VERSION 5.8 ;
BUSBITCHARS "[]" ;
DIVIDERCHAR "/" ;
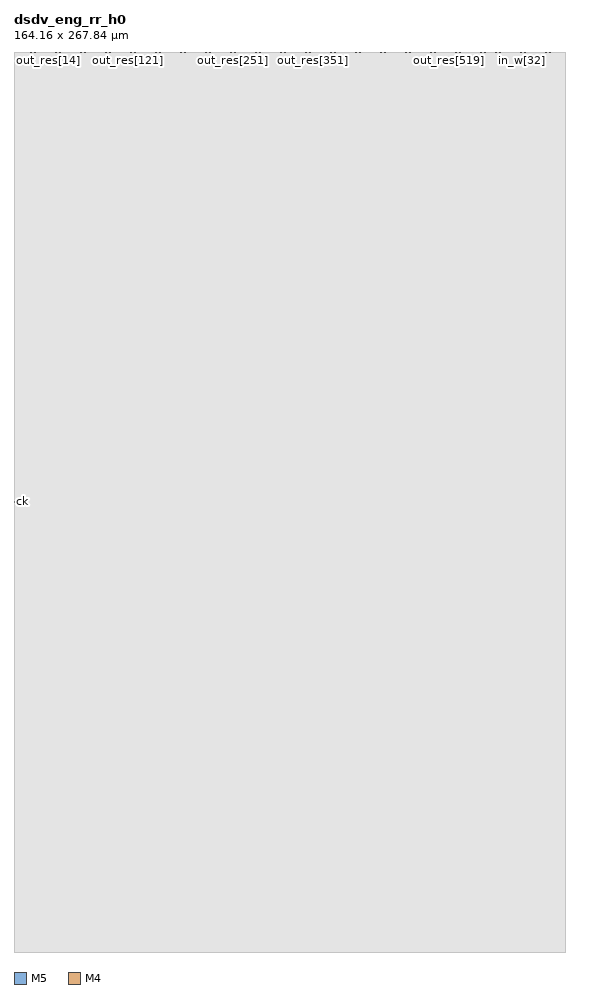
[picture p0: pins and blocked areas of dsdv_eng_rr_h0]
MACRO dsdv_eng_rr_h0
  CLASS BLOCK ;
  ORIGIN 0 0 ;
  FOREIGN dsdv_eng_rr_h0 0 0 ;
  SIZE 164.160 BY 267.840 ;
  SYMMETRY X Y ;
  PIN out_res[0]
    DIRECTION OUTPUT ;
    USE SIGNAL ;
    PORT
      LAYER M5 ;
        RECT 4.800 267.648 4.824 267.840 ;
    END
  END out_res[0]
  PIN out_res[1]
    DIRECTION OUTPUT ;
    USE SIGNAL ;
    PORT
      LAYER M5 ;
        RECT 5.040 267.648 5.064 267.840 ;
    END
  END out_res[1]
  PIN out_res[2]
    DIRECTION OUTPUT ;
    USE SIGNAL ;
    PORT
      LAYER M5 ;
        RECT 5.280 267.648 5.304 267.840 ;
    END
  END out_res[2]
  PIN out_res[3]
    DIRECTION OUTPUT ;
    USE SIGNAL ;
    PORT
      LAYER M5 ;
        RECT 5.520 267.648 5.544 267.840 ;
    END
  END out_res[3]
  PIN out_res[4]
    DIRECTION OUTPUT ;
    USE SIGNAL ;
    PORT
      LAYER M5 ;
        RECT 5.760 267.648 5.784 267.840 ;
    END
  END out_res[4]
  PIN out_res[5]
    DIRECTION OUTPUT ;
    USE SIGNAL ;
    PORT
      LAYER M5 ;
        RECT 6.000 267.648 6.024 267.840 ;
    END
  END out_res[5]
  PIN out_res[6]
    DIRECTION OUTPUT ;
    USE SIGNAL ;
    PORT
      LAYER M5 ;
        RECT 6.240 267.648 6.264 267.840 ;
    END
  END out_res[6]
  PIN out_res[7]
    DIRECTION OUTPUT ;
    USE SIGNAL ;
    PORT
      LAYER M5 ;
        RECT 6.480 267.648 6.504 267.840 ;
    END
  END out_res[7]
  PIN out_res[8]
    DIRECTION OUTPUT ;
    USE SIGNAL ;
    PORT
      LAYER M5 ;
        RECT 6.720 267.648 6.744 267.840 ;
    END
  END out_res[8]
  PIN out_res[9]
    DIRECTION OUTPUT ;
    USE SIGNAL ;
    PORT
      LAYER M5 ;
        RECT 6.960 267.648 6.984 267.840 ;
    END
  END out_res[9]
  PIN out_res[10]
    DIRECTION OUTPUT ;
    USE SIGNAL ;
    PORT
      LAYER M5 ;
        RECT 7.200 267.648 7.224 267.840 ;
    END
  END out_res[10]
  PIN out_res[11]
    DIRECTION OUTPUT ;
    USE SIGNAL ;
    PORT
      LAYER M5 ;
        RECT 7.440 267.648 7.464 267.840 ;
    END
  END out_res[11]
  PIN out_res[12]
    DIRECTION OUTPUT ;
    USE SIGNAL ;
    PORT
      LAYER M5 ;
        RECT 7.680 267.648 7.704 267.840 ;
    END
  END out_res[12]
  PIN out_res[13]
    DIRECTION OUTPUT ;
    USE SIGNAL ;
    PORT
      LAYER M5 ;
        RECT 7.920 267.648 7.944 267.840 ;
    END
  END out_res[13]
  PIN out_res[14]
    DIRECTION OUTPUT ;
    USE SIGNAL ;
    PORT
      LAYER M5 ;
        RECT 8.160 267.648 8.184 267.840 ;
    END
  END out_res[14]
  PIN out_res[15]
    DIRECTION OUTPUT ;
    USE SIGNAL ;
    PORT
      LAYER M5 ;
        RECT 8.400 267.648 8.424 267.840 ;
    END
  END out_res[15]
  PIN out_res[16]
    DIRECTION OUTPUT ;
    USE SIGNAL ;
    PORT
      LAYER M5 ;
        RECT 8.640 267.648 8.664 267.840 ;
    END
  END out_res[16]
  PIN out_res[17]
    DIRECTION OUTPUT ;
    USE SIGNAL ;
    PORT
      LAYER M5 ;
        RECT 8.880 267.648 8.904 267.840 ;
    END
  END out_res[17]
  PIN out_res[18]
    DIRECTION OUTPUT ;
    USE SIGNAL ;
    PORT
      LAYER M5 ;
        RECT 9.120 267.648 9.144 267.840 ;
    END
  END out_res[18]
  PIN out_res[19]
    DIRECTION OUTPUT ;
    USE SIGNAL ;
    PORT
      LAYER M5 ;
        RECT 9.360 267.648 9.384 267.840 ;
    END
  END out_res[19]
  PIN out_res[20]
    DIRECTION OUTPUT ;
    USE SIGNAL ;
    PORT
      LAYER M5 ;
        RECT 9.600 267.648 9.624 267.840 ;
    END
  END out_res[20]
  PIN out_res[21]
    DIRECTION OUTPUT ;
    USE SIGNAL ;
    PORT
      LAYER M5 ;
        RECT 9.840 267.648 9.864 267.840 ;
    END
  END out_res[21]
  PIN out_res[22]
    DIRECTION OUTPUT ;
    USE SIGNAL ;
    PORT
      LAYER M5 ;
        RECT 10.080 267.648 10.104 267.840 ;
    END
  END out_res[22]
  PIN out_res[23]
    DIRECTION OUTPUT ;
    USE SIGNAL ;
    PORT
      LAYER M5 ;
        RECT 10.320 267.648 10.344 267.840 ;
    END
  END out_res[23]
  PIN out_res[24]
    DIRECTION OUTPUT ;
    USE SIGNAL ;
    PORT
      LAYER M5 ;
        RECT 10.560 267.648 10.584 267.840 ;
    END
  END out_res[24]
  PIN out_res[25]
    DIRECTION OUTPUT ;
    USE SIGNAL ;
    PORT
      LAYER M5 ;
        RECT 10.800 267.648 10.824 267.840 ;
    END
  END out_res[25]
  PIN out_res[26]
    DIRECTION OUTPUT ;
    USE SIGNAL ;
    PORT
      LAYER M5 ;
        RECT 11.040 267.648 11.064 267.840 ;
    END
  END out_res[26]
  PIN out_res[27]
    DIRECTION OUTPUT ;
    USE SIGNAL ;
    PORT
      LAYER M5 ;
        RECT 11.280 267.648 11.304 267.840 ;
    END
  END out_res[27]
  PIN out_res[28]
    DIRECTION OUTPUT ;
    USE SIGNAL ;
    PORT
      LAYER M5 ;
        RECT 11.520 267.648 11.544 267.840 ;
    END
  END out_res[28]
  PIN out_res[29]
    DIRECTION OUTPUT ;
    USE SIGNAL ;
    PORT
      LAYER M5 ;
        RECT 11.760 267.648 11.784 267.840 ;
    END
  END out_res[29]
  PIN out_res[30]
    DIRECTION OUTPUT ;
    USE SIGNAL ;
    PORT
      LAYER M5 ;
        RECT 12.000 267.648 12.024 267.840 ;
    END
  END out_res[30]
  PIN out_res[31]
    DIRECTION OUTPUT ;
    USE SIGNAL ;
    PORT
      LAYER M5 ;
        RECT 12.240 267.648 12.264 267.840 ;
    END
  END out_res[31]
  PIN out_res[32]
    DIRECTION OUTPUT ;
    USE SIGNAL ;
    PORT
      LAYER M5 ;
        RECT 12.480 267.648 12.504 267.840 ;
    END
  END out_res[32]
  PIN out_res[33]
    DIRECTION OUTPUT ;
    USE SIGNAL ;
    PORT
      LAYER M5 ;
        RECT 12.720 267.648 12.744 267.840 ;
    END
  END out_res[33]
  PIN out_res[34]
    DIRECTION OUTPUT ;
    USE SIGNAL ;
    PORT
      LAYER M5 ;
        RECT 12.960 267.648 12.984 267.840 ;
    END
  END out_res[34]
  PIN out_res[35]
    DIRECTION OUTPUT ;
    USE SIGNAL ;
    PORT
      LAYER M5 ;
        RECT 13.200 267.648 13.224 267.840 ;
    END
  END out_res[35]
  PIN out_res[36]
    DIRECTION OUTPUT ;
    USE SIGNAL ;
    PORT
      LAYER M5 ;
        RECT 13.440 267.648 13.464 267.840 ;
    END
  END out_res[36]
  PIN out_res[37]
    DIRECTION OUTPUT ;
    USE SIGNAL ;
    PORT
      LAYER M5 ;
        RECT 13.680 267.648 13.704 267.840 ;
    END
  END out_res[37]
  PIN out_res[38]
    DIRECTION OUTPUT ;
    USE SIGNAL ;
    PORT
      LAYER M5 ;
        RECT 13.920 267.648 13.944 267.840 ;
    END
  END out_res[38]
  PIN out_res[39]
    DIRECTION OUTPUT ;
    USE SIGNAL ;
    PORT
      LAYER M5 ;
        RECT 14.160 267.648 14.184 267.840 ;
    END
  END out_res[39]
  PIN out_res[40]
    DIRECTION OUTPUT ;
    USE SIGNAL ;
    PORT
      LAYER M5 ;
        RECT 14.400 267.648 14.424 267.840 ;
    END
  END out_res[40]
  PIN out_res[41]
    DIRECTION OUTPUT ;
    USE SIGNAL ;
    PORT
      LAYER M5 ;
        RECT 14.640 267.648 14.664 267.840 ;
    END
  END out_res[41]
  PIN out_res[42]
    DIRECTION OUTPUT ;
    USE SIGNAL ;
    PORT
      LAYER M5 ;
        RECT 14.880 267.648 14.904 267.840 ;
    END
  END out_res[42]
  PIN out_res[43]
    DIRECTION OUTPUT ;
    USE SIGNAL ;
    PORT
      LAYER M5 ;
        RECT 15.120 267.648 15.144 267.840 ;
    END
  END out_res[43]
  PIN out_res[44]
    DIRECTION OUTPUT ;
    USE SIGNAL ;
    PORT
      LAYER M5 ;
        RECT 15.360 267.648 15.384 267.840 ;
    END
  END out_res[44]
  PIN out_res[45]
    DIRECTION OUTPUT ;
    USE SIGNAL ;
    PORT
      LAYER M5 ;
        RECT 15.600 267.648 15.624 267.840 ;
    END
  END out_res[45]
  PIN out_res[46]
    DIRECTION OUTPUT ;
    USE SIGNAL ;
    PORT
      LAYER M5 ;
        RECT 15.840 267.648 15.864 267.840 ;
    END
  END out_res[46]
  PIN out_res[47]
    DIRECTION OUTPUT ;
    USE SIGNAL ;
    PORT
      LAYER M5 ;
        RECT 16.080 267.648 16.104 267.840 ;
    END
  END out_res[47]
  PIN out_res[48]
    DIRECTION OUTPUT ;
    USE SIGNAL ;
    PORT
      LAYER M5 ;
        RECT 16.320 267.648 16.344 267.840 ;
    END
  END out_res[48]
  PIN out_res[49]
    DIRECTION OUTPUT ;
    USE SIGNAL ;
    PORT
      LAYER M5 ;
        RECT 16.560 267.648 16.584 267.840 ;
    END
  END out_res[49]
  PIN out_res[50]
    DIRECTION OUTPUT ;
    USE SIGNAL ;
    PORT
      LAYER M5 ;
        RECT 16.800 267.648 16.824 267.840 ;
    END
  END out_res[50]
  PIN out_res[51]
    DIRECTION OUTPUT ;
    USE SIGNAL ;
    PORT
      LAYER M5 ;
        RECT 17.040 267.648 17.064 267.840 ;
    END
  END out_res[51]
  PIN out_res[52]
    DIRECTION OUTPUT ;
    USE SIGNAL ;
    PORT
      LAYER M5 ;
        RECT 17.280 267.648 17.304 267.840 ;
    END
  END out_res[52]
  PIN out_res[53]
    DIRECTION OUTPUT ;
    USE SIGNAL ;
    PORT
      LAYER M5 ;
        RECT 17.520 267.648 17.544 267.840 ;
    END
  END out_res[53]
  PIN out_res[54]
    DIRECTION OUTPUT ;
    USE SIGNAL ;
    PORT
      LAYER M5 ;
        RECT 17.760 267.648 17.784 267.840 ;
    END
  END out_res[54]
  PIN out_res[55]
    DIRECTION OUTPUT ;
    USE SIGNAL ;
    PORT
      LAYER M5 ;
        RECT 18.000 267.648 18.024 267.840 ;
    END
  END out_res[55]
  PIN out_res[56]
    DIRECTION OUTPUT ;
    USE SIGNAL ;
    PORT
      LAYER M5 ;
        RECT 18.240 267.648 18.264 267.840 ;
    END
  END out_res[56]
  PIN out_res[57]
    DIRECTION OUTPUT ;
    USE SIGNAL ;
    PORT
      LAYER M5 ;
        RECT 18.480 267.648 18.504 267.840 ;
    END
  END out_res[57]
  PIN out_res[58]
    DIRECTION OUTPUT ;
    USE SIGNAL ;
    PORT
      LAYER M5 ;
        RECT 18.720 267.648 18.744 267.840 ;
    END
  END out_res[58]
  PIN out_res[59]
    DIRECTION OUTPUT ;
    USE SIGNAL ;
    PORT
      LAYER M5 ;
        RECT 18.960 267.648 18.984 267.840 ;
    END
  END out_res[59]
  PIN out_res[60]
    DIRECTION OUTPUT ;
    USE SIGNAL ;
    PORT
      LAYER M5 ;
        RECT 19.200 267.648 19.224 267.840 ;
    END
  END out_res[60]
  PIN out_res[61]
    DIRECTION OUTPUT ;
    USE SIGNAL ;
    PORT
      LAYER M5 ;
        RECT 19.440 267.648 19.464 267.840 ;
    END
  END out_res[61]
  PIN out_res[62]
    DIRECTION OUTPUT ;
    USE SIGNAL ;
    PORT
      LAYER M5 ;
        RECT 19.680 267.648 19.704 267.840 ;
    END
  END out_res[62]
  PIN out_res[63]
    DIRECTION OUTPUT ;
    USE SIGNAL ;
    PORT
      LAYER M5 ;
        RECT 19.920 267.648 19.944 267.840 ;
    END
  END out_res[63]
  PIN out_res[64]
    DIRECTION OUTPUT ;
    USE SIGNAL ;
    PORT
      LAYER M5 ;
        RECT 20.160 267.648 20.184 267.840 ;
    END
  END out_res[64]
  PIN out_res[65]
    DIRECTION OUTPUT ;
    USE SIGNAL ;
    PORT
      LAYER M5 ;
        RECT 20.400 267.648 20.424 267.840 ;
    END
  END out_res[65]
  PIN out_res[66]
    DIRECTION OUTPUT ;
    USE SIGNAL ;
    PORT
      LAYER M5 ;
        RECT 20.640 267.648 20.664 267.840 ;
    END
  END out_res[66]
  PIN out_res[67]
    DIRECTION OUTPUT ;
    USE SIGNAL ;
    PORT
      LAYER M5 ;
        RECT 20.880 267.648 20.904 267.840 ;
    END
  END out_res[67]
  PIN out_res[68]
    DIRECTION OUTPUT ;
    USE SIGNAL ;
    PORT
      LAYER M5 ;
        RECT 21.120 267.648 21.144 267.840 ;
    END
  END out_res[68]
  PIN out_res[69]
    DIRECTION OUTPUT ;
    USE SIGNAL ;
    PORT
      LAYER M5 ;
        RECT 21.360 267.648 21.384 267.840 ;
    END
  END out_res[69]
  PIN out_res[70]
    DIRECTION OUTPUT ;
    USE SIGNAL ;
    PORT
      LAYER M5 ;
        RECT 21.600 267.648 21.624 267.840 ;
    END
  END out_res[70]
  PIN out_res[71]
    DIRECTION OUTPUT ;
    USE SIGNAL ;
    PORT
      LAYER M5 ;
        RECT 21.840 267.648 21.864 267.840 ;
    END
  END out_res[71]
  PIN out_res[72]
    DIRECTION OUTPUT ;
    USE SIGNAL ;
    PORT
      LAYER M5 ;
        RECT 22.080 267.648 22.104 267.840 ;
    END
  END out_res[72]
  PIN out_res[73]
    DIRECTION OUTPUT ;
    USE SIGNAL ;
    PORT
      LAYER M5 ;
        RECT 22.320 267.648 22.344 267.840 ;
    END
  END out_res[73]
  PIN out_res[74]
    DIRECTION OUTPUT ;
    USE SIGNAL ;
    PORT
      LAYER M5 ;
        RECT 22.560 267.648 22.584 267.840 ;
    END
  END out_res[74]
  PIN out_res[75]
    DIRECTION OUTPUT ;
    USE SIGNAL ;
    PORT
      LAYER M5 ;
        RECT 22.800 267.648 22.824 267.840 ;
    END
  END out_res[75]
  PIN out_res[76]
    DIRECTION OUTPUT ;
    USE SIGNAL ;
    PORT
      LAYER M5 ;
        RECT 23.040 267.648 23.064 267.840 ;
    END
  END out_res[76]
  PIN out_res[77]
    DIRECTION OUTPUT ;
    USE SIGNAL ;
    PORT
      LAYER M5 ;
        RECT 23.280 267.648 23.304 267.840 ;
    END
  END out_res[77]
  PIN out_res[78]
    DIRECTION OUTPUT ;
    USE SIGNAL ;
    PORT
      LAYER M5 ;
        RECT 23.520 267.648 23.544 267.840 ;
    END
  END out_res[78]
  PIN out_res[79]
    DIRECTION OUTPUT ;
    USE SIGNAL ;
    PORT
      LAYER M5 ;
        RECT 23.760 267.648 23.784 267.840 ;
    END
  END out_res[79]
  PIN out_res[80]
    DIRECTION OUTPUT ;
    USE SIGNAL ;
    PORT
      LAYER M5 ;
        RECT 24.000 267.648 24.024 267.840 ;
    END
  END out_res[80]
  PIN out_res[81]
    DIRECTION OUTPUT ;
    USE SIGNAL ;
    PORT
      LAYER M5 ;
        RECT 24.240 267.648 24.264 267.840 ;
    END
  END out_res[81]
  PIN out_res[82]
    DIRECTION OUTPUT ;
    USE SIGNAL ;
    PORT
      LAYER M5 ;
        RECT 24.480 267.648 24.504 267.840 ;
    END
  END out_res[82]
  PIN out_res[83]
    DIRECTION OUTPUT ;
    USE SIGNAL ;
    PORT
      LAYER M5 ;
        RECT 24.720 267.648 24.744 267.840 ;
    END
  END out_res[83]
  PIN out_res[84]
    DIRECTION OUTPUT ;
    USE SIGNAL ;
    PORT
      LAYER M5 ;
        RECT 24.960 267.648 24.984 267.840 ;
    END
  END out_res[84]
  PIN out_res[85]
    DIRECTION OUTPUT ;
    USE SIGNAL ;
    PORT
      LAYER M5 ;
        RECT 25.200 267.648 25.224 267.840 ;
    END
  END out_res[85]
  PIN out_res[86]
    DIRECTION OUTPUT ;
    USE SIGNAL ;
    PORT
      LAYER M5 ;
        RECT 25.440 267.648 25.464 267.840 ;
    END
  END out_res[86]
  PIN out_res[87]
    DIRECTION OUTPUT ;
    USE SIGNAL ;
    PORT
      LAYER M5 ;
        RECT 25.680 267.648 25.704 267.840 ;
    END
  END out_res[87]
  PIN out_res[88]
    DIRECTION OUTPUT ;
    USE SIGNAL ;
    PORT
      LAYER M5 ;
        RECT 25.920 267.648 25.944 267.840 ;
    END
  END out_res[88]
  PIN out_res[89]
    DIRECTION OUTPUT ;
    USE SIGNAL ;
    PORT
      LAYER M5 ;
        RECT 26.160 267.648 26.184 267.840 ;
    END
  END out_res[89]
  PIN out_res[90]
    DIRECTION OUTPUT ;
    USE SIGNAL ;
    PORT
      LAYER M5 ;
        RECT 26.400 267.648 26.424 267.840 ;
    END
  END out_res[90]
  PIN out_res[91]
    DIRECTION OUTPUT ;
    USE SIGNAL ;
    PORT
      LAYER M5 ;
        RECT 26.640 267.648 26.664 267.840 ;
    END
  END out_res[91]
  PIN out_res[92]
    DIRECTION OUTPUT ;
    USE SIGNAL ;
    PORT
      LAYER M5 ;
        RECT 26.880 267.648 26.904 267.840 ;
    END
  END out_res[92]
  PIN out_res[93]
    DIRECTION OUTPUT ;
    USE SIGNAL ;
    PORT
      LAYER M5 ;
        RECT 27.120 267.648 27.144 267.840 ;
    END
  END out_res[93]
  PIN out_res[94]
    DIRECTION OUTPUT ;
    USE SIGNAL ;
    PORT
      LAYER M5 ;
        RECT 27.360 267.648 27.384 267.840 ;
    END
  END out_res[94]
  PIN out_res[95]
    DIRECTION OUTPUT ;
    USE SIGNAL ;
    PORT
      LAYER M5 ;
        RECT 27.600 267.648 27.624 267.840 ;
    END
  END out_res[95]
  PIN out_res[96]
    DIRECTION OUTPUT ;
    USE SIGNAL ;
    PORT
      LAYER M5 ;
        RECT 27.840 267.648 27.864 267.840 ;
    END
  END out_res[96]
  PIN out_res[97]
    DIRECTION OUTPUT ;
    USE SIGNAL ;
    PORT
      LAYER M5 ;
        RECT 28.080 267.648 28.104 267.840 ;
    END
  END out_res[97]
  PIN out_res[98]
    DIRECTION OUTPUT ;
    USE SIGNAL ;
    PORT
      LAYER M5 ;
        RECT 28.320 267.648 28.344 267.840 ;
    END
  END out_res[98]
  PIN out_res[99]
    DIRECTION OUTPUT ;
    USE SIGNAL ;
    PORT
      LAYER M5 ;
        RECT 28.560 267.648 28.584 267.840 ;
    END
  END out_res[99]
  PIN out_res[100]
    DIRECTION OUTPUT ;
    USE SIGNAL ;
    PORT
      LAYER M5 ;
        RECT 28.800 267.648 28.824 267.840 ;
    END
  END out_res[100]
  PIN out_res[101]
    DIRECTION OUTPUT ;
    USE SIGNAL ;
    PORT
      LAYER M5 ;
        RECT 29.040 267.648 29.064 267.840 ;
    END
  END out_res[101]
  PIN out_res[102]
    DIRECTION OUTPUT ;
    USE SIGNAL ;
    PORT
      LAYER M5 ;
        RECT 29.280 267.648 29.304 267.840 ;
    END
  END out_res[102]
  PIN out_res[103]
    DIRECTION OUTPUT ;
    USE SIGNAL ;
    PORT
      LAYER M5 ;
        RECT 29.520 267.648 29.544 267.840 ;
    END
  END out_res[103]
  PIN out_res[104]
    DIRECTION OUTPUT ;
    USE SIGNAL ;
    PORT
      LAYER M5 ;
        RECT 29.760 267.648 29.784 267.840 ;
    END
  END out_res[104]
  PIN out_res[105]
    DIRECTION OUTPUT ;
    USE SIGNAL ;
    PORT
      LAYER M5 ;
        RECT 30.000 267.648 30.024 267.840 ;
    END
  END out_res[105]
  PIN out_res[106]
    DIRECTION OUTPUT ;
    USE SIGNAL ;
    PORT
      LAYER M5 ;
        RECT 30.240 267.648 30.264 267.840 ;
    END
  END out_res[106]
  PIN out_res[107]
    DIRECTION OUTPUT ;
    USE SIGNAL ;
    PORT
      LAYER M5 ;
        RECT 30.480 267.648 30.504 267.840 ;
    END
  END out_res[107]
  PIN out_res[108]
    DIRECTION OUTPUT ;
    USE SIGNAL ;
    PORT
      LAYER M5 ;
        RECT 30.720 267.648 30.744 267.840 ;
    END
  END out_res[108]
  PIN out_res[109]
    DIRECTION OUTPUT ;
    USE SIGNAL ;
    PORT
      LAYER M5 ;
        RECT 30.960 267.648 30.984 267.840 ;
    END
  END out_res[109]
  PIN out_res[110]
    DIRECTION OUTPUT ;
    USE SIGNAL ;
    PORT
      LAYER M5 ;
        RECT 31.200 267.648 31.224 267.840 ;
    END
  END out_res[110]
  PIN out_res[111]
    DIRECTION OUTPUT ;
    USE SIGNAL ;
    PORT
      LAYER M5 ;
        RECT 31.440 267.648 31.464 267.840 ;
    END
  END out_res[111]
  PIN out_res[112]
    DIRECTION OUTPUT ;
    USE SIGNAL ;
    PORT
      LAYER M5 ;
        RECT 31.680 267.648 31.704 267.840 ;
    END
  END out_res[112]
  PIN out_res[113]
    DIRECTION OUTPUT ;
    USE SIGNAL ;
    PORT
      LAYER M5 ;
        RECT 31.920 267.648 31.944 267.840 ;
    END
  END out_res[113]
  PIN out_res[114]
    DIRECTION OUTPUT ;
    USE SIGNAL ;
    PORT
      LAYER M5 ;
        RECT 32.160 267.648 32.184 267.840 ;
    END
  END out_res[114]
  PIN out_res[115]
    DIRECTION OUTPUT ;
    USE SIGNAL ;
    PORT
      LAYER M5 ;
        RECT 32.400 267.648 32.424 267.840 ;
    END
  END out_res[115]
  PIN out_res[116]
    DIRECTION OUTPUT ;
    USE SIGNAL ;
    PORT
      LAYER M5 ;
        RECT 32.640 267.648 32.664 267.840 ;
    END
  END out_res[116]
  PIN out_res[117]
    DIRECTION OUTPUT ;
    USE SIGNAL ;
    PORT
      LAYER M5 ;
        RECT 32.880 267.648 32.904 267.840 ;
    END
  END out_res[117]
  PIN out_res[118]
    DIRECTION OUTPUT ;
    USE SIGNAL ;
    PORT
      LAYER M5 ;
        RECT 33.120 267.648 33.144 267.840 ;
    END
  END out_res[118]
  PIN out_res[119]
    DIRECTION OUTPUT ;
    USE SIGNAL ;
    PORT
      LAYER M5 ;
        RECT 33.360 267.648 33.384 267.840 ;
    END
  END out_res[119]
  PIN out_res[120]
    DIRECTION OUTPUT ;
    USE SIGNAL ;
    PORT
      LAYER M5 ;
        RECT 33.600 267.648 33.624 267.840 ;
    END
  END out_res[120]
  PIN out_res[121]
    DIRECTION OUTPUT ;
    USE SIGNAL ;
    PORT
      LAYER M5 ;
        RECT 33.840 267.648 33.864 267.840 ;
    END
  END out_res[121]
  PIN out_res[122]
    DIRECTION OUTPUT ;
    USE SIGNAL ;
    PORT
      LAYER M5 ;
        RECT 34.080 267.648 34.104 267.840 ;
    END
  END out_res[122]
  PIN out_res[123]
    DIRECTION OUTPUT ;
    USE SIGNAL ;
    PORT
      LAYER M5 ;
        RECT 34.320 267.648 34.344 267.840 ;
    END
  END out_res[123]
  PIN out_res[124]
    DIRECTION OUTPUT ;
    USE SIGNAL ;
    PORT
      LAYER M5 ;
        RECT 34.560 267.648 34.584 267.840 ;
    END
  END out_res[124]
  PIN out_res[125]
    DIRECTION OUTPUT ;
    USE SIGNAL ;
    PORT
      LAYER M5 ;
        RECT 34.800 267.648 34.824 267.840 ;
    END
  END out_res[125]
  PIN out_res[126]
    DIRECTION OUTPUT ;
    USE SIGNAL ;
    PORT
      LAYER M5 ;
        RECT 35.040 267.648 35.064 267.840 ;
    END
  END out_res[126]
  PIN out_res[127]
    DIRECTION OUTPUT ;
    USE SIGNAL ;
    PORT
      LAYER M5 ;
        RECT 35.280 267.648 35.304 267.840 ;
    END
  END out_res[127]
  PIN out_res[128]
    DIRECTION OUTPUT ;
    USE SIGNAL ;
    PORT
      LAYER M5 ;
        RECT 35.520 267.648 35.544 267.840 ;
    END
  END out_res[128]
  PIN out_res[129]
    DIRECTION OUTPUT ;
    USE SIGNAL ;
    PORT
      LAYER M5 ;
        RECT 35.760 267.648 35.784 267.840 ;
    END
  END out_res[129]
  PIN out_res[130]
    DIRECTION OUTPUT ;
    USE SIGNAL ;
    PORT
      LAYER M5 ;
        RECT 36.000 267.648 36.024 267.840 ;
    END
  END out_res[130]
  PIN out_res[131]
    DIRECTION OUTPUT ;
    USE SIGNAL ;
    PORT
      LAYER M5 ;
        RECT 36.240 267.648 36.264 267.840 ;
    END
  END out_res[131]
  PIN out_res[132]
    DIRECTION OUTPUT ;
    USE SIGNAL ;
    PORT
      LAYER M5 ;
        RECT 36.480 267.648 36.504 267.840 ;
    END
  END out_res[132]
  PIN out_res[133]
    DIRECTION OUTPUT ;
    USE SIGNAL ;
    PORT
      LAYER M5 ;
        RECT 36.720 267.648 36.744 267.840 ;
    END
  END out_res[133]
  PIN out_res[134]
    DIRECTION OUTPUT ;
    USE SIGNAL ;
    PORT
      LAYER M5 ;
        RECT 36.960 267.648 36.984 267.840 ;
    END
  END out_res[134]
  PIN out_res[135]
    DIRECTION OUTPUT ;
    USE SIGNAL ;
    PORT
      LAYER M5 ;
        RECT 37.200 267.648 37.224 267.840 ;
    END
  END out_res[135]
  PIN out_res[136]
    DIRECTION OUTPUT ;
    USE SIGNAL ;
    PORT
      LAYER M5 ;
        RECT 37.440 267.648 37.464 267.840 ;
    END
  END out_res[136]
  PIN out_res[137]
    DIRECTION OUTPUT ;
    USE SIGNAL ;
    PORT
      LAYER M5 ;
        RECT 37.680 267.648 37.704 267.840 ;
    END
  END out_res[137]
  PIN out_res[138]
    DIRECTION OUTPUT ;
    USE SIGNAL ;
    PORT
      LAYER M5 ;
        RECT 37.920 267.648 37.944 267.840 ;
    END
  END out_res[138]
  PIN out_res[139]
    DIRECTION OUTPUT ;
    USE SIGNAL ;
    PORT
      LAYER M5 ;
        RECT 38.160 267.648 38.184 267.840 ;
    END
  END out_res[139]
  PIN out_res[140]
    DIRECTION OUTPUT ;
    USE SIGNAL ;
    PORT
      LAYER M5 ;
        RECT 38.400 267.648 38.424 267.840 ;
    END
  END out_res[140]
  PIN out_res[141]
    DIRECTION OUTPUT ;
    USE SIGNAL ;
    PORT
      LAYER M5 ;
        RECT 38.640 267.648 38.664 267.840 ;
    END
  END out_res[141]
  PIN out_res[142]
    DIRECTION OUTPUT ;
    USE SIGNAL ;
    PORT
      LAYER M5 ;
        RECT 38.880 267.648 38.904 267.840 ;
    END
  END out_res[142]
  PIN out_res[143]
    DIRECTION OUTPUT ;
    USE SIGNAL ;
    PORT
      LAYER M5 ;
        RECT 39.120 267.648 39.144 267.840 ;
    END
  END out_res[143]
  PIN out_res[144]
    DIRECTION OUTPUT ;
    USE SIGNAL ;
    PORT
      LAYER M5 ;
        RECT 39.360 267.648 39.384 267.840 ;
    END
  END out_res[144]
  PIN out_res[145]
    DIRECTION OUTPUT ;
    USE SIGNAL ;
    PORT
      LAYER M5 ;
        RECT 39.600 267.648 39.624 267.840 ;
    END
  END out_res[145]
  PIN out_res[146]
    DIRECTION OUTPUT ;
    USE SIGNAL ;
    PORT
      LAYER M5 ;
        RECT 39.840 267.648 39.864 267.840 ;
    END
  END out_res[146]
  PIN out_res[147]
    DIRECTION OUTPUT ;
    USE SIGNAL ;
    PORT
      LAYER M5 ;
        RECT 40.080 267.648 40.104 267.840 ;
    END
  END out_res[147]
  PIN out_res[148]
    DIRECTION OUTPUT ;
    USE SIGNAL ;
    PORT
      LAYER M5 ;
        RECT 40.320 267.648 40.344 267.840 ;
    END
  END out_res[148]
  PIN out_res[149]
    DIRECTION OUTPUT ;
    USE SIGNAL ;
    PORT
      LAYER M5 ;
        RECT 40.560 267.648 40.584 267.840 ;
    END
  END out_res[149]
  PIN out_res[150]
    DIRECTION OUTPUT ;
    USE SIGNAL ;
    PORT
      LAYER M5 ;
        RECT 40.800 267.648 40.824 267.840 ;
    END
  END out_res[150]
  PIN out_res[151]
    DIRECTION OUTPUT ;
    USE SIGNAL ;
    PORT
      LAYER M5 ;
        RECT 41.040 267.648 41.064 267.840 ;
    END
  END out_res[151]
  PIN out_res[152]
    DIRECTION OUTPUT ;
    USE SIGNAL ;
    PORT
      LAYER M5 ;
        RECT 41.280 267.648 41.304 267.840 ;
    END
  END out_res[152]
  PIN out_res[153]
    DIRECTION OUTPUT ;
    USE SIGNAL ;
    PORT
      LAYER M5 ;
        RECT 41.520 267.648 41.544 267.840 ;
    END
  END out_res[153]
  PIN out_res[154]
    DIRECTION OUTPUT ;
    USE SIGNAL ;
    PORT
      LAYER M5 ;
        RECT 41.760 267.648 41.784 267.840 ;
    END
  END out_res[154]
  PIN out_res[155]
    DIRECTION OUTPUT ;
    USE SIGNAL ;
    PORT
      LAYER M5 ;
        RECT 42.000 267.648 42.024 267.840 ;
    END
  END out_res[155]
  PIN out_res[156]
    DIRECTION OUTPUT ;
    USE SIGNAL ;
    PORT
      LAYER M5 ;
        RECT 42.240 267.648 42.264 267.840 ;
    END
  END out_res[156]
  PIN out_res[157]
    DIRECTION OUTPUT ;
    USE SIGNAL ;
    PORT
      LAYER M5 ;
        RECT 42.480 267.648 42.504 267.840 ;
    END
  END out_res[157]
  PIN out_res[158]
    DIRECTION OUTPUT ;
    USE SIGNAL ;
    PORT
      LAYER M5 ;
        RECT 42.720 267.648 42.744 267.840 ;
    END
  END out_res[158]
  PIN out_res[159]
    DIRECTION OUTPUT ;
    USE SIGNAL ;
    PORT
      LAYER M5 ;
        RECT 42.960 267.648 42.984 267.840 ;
    END
  END out_res[159]
  PIN out_res[160]
    DIRECTION OUTPUT ;
    USE SIGNAL ;
    PORT
      LAYER M5 ;
        RECT 43.200 267.648 43.224 267.840 ;
    END
  END out_res[160]
  PIN out_res[161]
    DIRECTION OUTPUT ;
    USE SIGNAL ;
    PORT
      LAYER M5 ;
        RECT 43.440 267.648 43.464 267.840 ;
    END
  END out_res[161]
  PIN out_res[162]
    DIRECTION OUTPUT ;
    USE SIGNAL ;
    PORT
      LAYER M5 ;
        RECT 43.680 267.648 43.704 267.840 ;
    END
  END out_res[162]
  PIN out_res[163]
    DIRECTION OUTPUT ;
    USE SIGNAL ;
    PORT
      LAYER M5 ;
        RECT 43.920 267.648 43.944 267.840 ;
    END
  END out_res[163]
  PIN out_res[164]
    DIRECTION OUTPUT ;
    USE SIGNAL ;
    PORT
      LAYER M5 ;
        RECT 44.160 267.648 44.184 267.840 ;
    END
  END out_res[164]
  PIN out_res[165]
    DIRECTION OUTPUT ;
    USE SIGNAL ;
    PORT
      LAYER M5 ;
        RECT 44.400 267.648 44.424 267.840 ;
    END
  END out_res[165]
  PIN out_res[166]
    DIRECTION OUTPUT ;
    USE SIGNAL ;
    PORT
      LAYER M5 ;
        RECT 44.640 267.648 44.664 267.840 ;
    END
  END out_res[166]
  PIN out_res[167]
    DIRECTION OUTPUT ;
    USE SIGNAL ;
    PORT
      LAYER M5 ;
        RECT 44.880 267.648 44.904 267.840 ;
    END
  END out_res[167]
  PIN out_res[168]
    DIRECTION OUTPUT ;
    USE SIGNAL ;
    PORT
      LAYER M5 ;
        RECT 45.120 267.648 45.144 267.840 ;
    END
  END out_res[168]
  PIN out_res[169]
    DIRECTION OUTPUT ;
    USE SIGNAL ;
    PORT
      LAYER M5 ;
        RECT 45.360 267.648 45.384 267.840 ;
    END
  END out_res[169]
  PIN out_res[170]
    DIRECTION OUTPUT ;
    USE SIGNAL ;
    PORT
      LAYER M5 ;
        RECT 45.600 267.648 45.624 267.840 ;
    END
  END out_res[170]
  PIN out_res[171]
    DIRECTION OUTPUT ;
    USE SIGNAL ;
    PORT
      LAYER M5 ;
        RECT 45.840 267.648 45.864 267.840 ;
    END
  END out_res[171]
  PIN out_res[172]
    DIRECTION OUTPUT ;
    USE SIGNAL ;
    PORT
      LAYER M5 ;
        RECT 46.080 267.648 46.104 267.840 ;
    END
  END out_res[172]
  PIN out_res[173]
    DIRECTION OUTPUT ;
    USE SIGNAL ;
    PORT
      LAYER M5 ;
        RECT 46.320 267.648 46.344 267.840 ;
    END
  END out_res[173]
  PIN out_res[174]
    DIRECTION OUTPUT ;
    USE SIGNAL ;
    PORT
      LAYER M5 ;
        RECT 46.560 267.648 46.584 267.840 ;
    END
  END out_res[174]
  PIN out_res[175]
    DIRECTION OUTPUT ;
    USE SIGNAL ;
    PORT
      LAYER M5 ;
        RECT 46.800 267.648 46.824 267.840 ;
    END
  END out_res[175]
  PIN out_res[176]
    DIRECTION OUTPUT ;
    USE SIGNAL ;
    PORT
      LAYER M5 ;
        RECT 47.040 267.648 47.064 267.840 ;
    END
  END out_res[176]
  PIN out_res[177]
    DIRECTION OUTPUT ;
    USE SIGNAL ;
    PORT
      LAYER M5 ;
        RECT 47.280 267.648 47.304 267.840 ;
    END
  END out_res[177]
  PIN out_res[178]
    DIRECTION OUTPUT ;
    USE SIGNAL ;
    PORT
      LAYER M5 ;
        RECT 47.520 267.648 47.544 267.840 ;
    END
  END out_res[178]
  PIN out_res[179]
    DIRECTION OUTPUT ;
    USE SIGNAL ;
    PORT
      LAYER M5 ;
        RECT 47.760 267.648 47.784 267.840 ;
    END
  END out_res[179]
  PIN out_res[180]
    DIRECTION OUTPUT ;
    USE SIGNAL ;
    PORT
      LAYER M5 ;
        RECT 48.000 267.648 48.024 267.840 ;
    END
  END out_res[180]
  PIN out_res[181]
    DIRECTION OUTPUT ;
    USE SIGNAL ;
    PORT
      LAYER M5 ;
        RECT 48.240 267.648 48.264 267.840 ;
    END
  END out_res[181]
  PIN out_res[182]
    DIRECTION OUTPUT ;
    USE SIGNAL ;
    PORT
      LAYER M5 ;
        RECT 48.480 267.648 48.504 267.840 ;
    END
  END out_res[182]
  PIN out_res[183]
    DIRECTION OUTPUT ;
    USE SIGNAL ;
    PORT
      LAYER M5 ;
        RECT 48.720 267.648 48.744 267.840 ;
    END
  END out_res[183]
  PIN out_res[184]
    DIRECTION OUTPUT ;
    USE SIGNAL ;
    PORT
      LAYER M5 ;
        RECT 48.960 267.648 48.984 267.840 ;
    END
  END out_res[184]
  PIN out_res[185]
    DIRECTION OUTPUT ;
    USE SIGNAL ;
    PORT
      LAYER M5 ;
        RECT 49.200 267.648 49.224 267.840 ;
    END
  END out_res[185]
  PIN out_res[186]
    DIRECTION OUTPUT ;
    USE SIGNAL ;
    PORT
      LAYER M5 ;
        RECT 49.440 267.648 49.464 267.840 ;
    END
  END out_res[186]
  PIN out_res[187]
    DIRECTION OUTPUT ;
    USE SIGNAL ;
    PORT
      LAYER M5 ;
        RECT 49.680 267.648 49.704 267.840 ;
    END
  END out_res[187]
  PIN out_res[188]
    DIRECTION OUTPUT ;
    USE SIGNAL ;
    PORT
      LAYER M5 ;
        RECT 49.920 267.648 49.944 267.840 ;
    END
  END out_res[188]
  PIN out_res[189]
    DIRECTION OUTPUT ;
    USE SIGNAL ;
    PORT
      LAYER M5 ;
        RECT 50.160 267.648 50.184 267.840 ;
    END
  END out_res[189]
  PIN out_res[190]
    DIRECTION OUTPUT ;
    USE SIGNAL ;
    PORT
      LAYER M5 ;
        RECT 50.400 267.648 50.424 267.840 ;
    END
  END out_res[190]
  PIN out_res[191]
    DIRECTION OUTPUT ;
    USE SIGNAL ;
    PORT
      LAYER M5 ;
        RECT 50.640 267.648 50.664 267.840 ;
    END
  END out_res[191]
  PIN out_res[192]
    DIRECTION OUTPUT ;
    USE SIGNAL ;
    PORT
      LAYER M5 ;
        RECT 50.880 267.648 50.904 267.840 ;
    END
  END out_res[192]
  PIN out_res[193]
    DIRECTION OUTPUT ;
    USE SIGNAL ;
    PORT
      LAYER M5 ;
        RECT 51.120 267.648 51.144 267.840 ;
    END
  END out_res[193]
  PIN out_res[194]
    DIRECTION OUTPUT ;
    USE SIGNAL ;
    PORT
      LAYER M5 ;
        RECT 51.360 267.648 51.384 267.840 ;
    END
  END out_res[194]
  PIN out_res[195]
    DIRECTION OUTPUT ;
    USE SIGNAL ;
    PORT
      LAYER M5 ;
        RECT 51.600 267.648 51.624 267.840 ;
    END
  END out_res[195]
  PIN out_res[196]
    DIRECTION OUTPUT ;
    USE SIGNAL ;
    PORT
      LAYER M5 ;
        RECT 51.840 267.648 51.864 267.840 ;
    END
  END out_res[196]
  PIN out_res[197]
    DIRECTION OUTPUT ;
    USE SIGNAL ;
    PORT
      LAYER M5 ;
        RECT 52.080 267.648 52.104 267.840 ;
    END
  END out_res[197]
  PIN out_res[198]
    DIRECTION OUTPUT ;
    USE SIGNAL ;
    PORT
      LAYER M5 ;
        RECT 52.320 267.648 52.344 267.840 ;
    END
  END out_res[198]
  PIN out_res[199]
    DIRECTION OUTPUT ;
    USE SIGNAL ;
    PORT
      LAYER M5 ;
        RECT 52.560 267.648 52.584 267.840 ;
    END
  END out_res[199]
  PIN out_res[200]
    DIRECTION OUTPUT ;
    USE SIGNAL ;
    PORT
      LAYER M5 ;
        RECT 52.800 267.648 52.824 267.840 ;
    END
  END out_res[200]
  PIN out_res[201]
    DIRECTION OUTPUT ;
    USE SIGNAL ;
    PORT
      LAYER M5 ;
        RECT 53.040 267.648 53.064 267.840 ;
    END
  END out_res[201]
  PIN out_res[202]
    DIRECTION OUTPUT ;
    USE SIGNAL ;
    PORT
      LAYER M5 ;
        RECT 53.280 267.648 53.304 267.840 ;
    END
  END out_res[202]
  PIN out_res[203]
    DIRECTION OUTPUT ;
    USE SIGNAL ;
    PORT
      LAYER M5 ;
        RECT 53.520 267.648 53.544 267.840 ;
    END
  END out_res[203]
  PIN out_res[204]
    DIRECTION OUTPUT ;
    USE SIGNAL ;
    PORT
      LAYER M5 ;
        RECT 53.760 267.648 53.784 267.840 ;
    END
  END out_res[204]
  PIN out_res[205]
    DIRECTION OUTPUT ;
    USE SIGNAL ;
    PORT
      LAYER M5 ;
        RECT 54.000 267.648 54.024 267.840 ;
    END
  END out_res[205]
  PIN out_res[206]
    DIRECTION OUTPUT ;
    USE SIGNAL ;
    PORT
      LAYER M5 ;
        RECT 54.240 267.648 54.264 267.840 ;
    END
  END out_res[206]
  PIN out_res[207]
    DIRECTION OUTPUT ;
    USE SIGNAL ;
    PORT
      LAYER M5 ;
        RECT 54.480 267.648 54.504 267.840 ;
    END
  END out_res[207]
  PIN out_res[208]
    DIRECTION OUTPUT ;
    USE SIGNAL ;
    PORT
      LAYER M5 ;
        RECT 54.720 267.648 54.744 267.840 ;
    END
  END out_res[208]
  PIN out_res[209]
    DIRECTION OUTPUT ;
    USE SIGNAL ;
    PORT
      LAYER M5 ;
        RECT 54.960 267.648 54.984 267.840 ;
    END
  END out_res[209]
  PIN out_res[210]
    DIRECTION OUTPUT ;
    USE SIGNAL ;
    PORT
      LAYER M5 ;
        RECT 55.200 267.648 55.224 267.840 ;
    END
  END out_res[210]
  PIN out_res[211]
    DIRECTION OUTPUT ;
    USE SIGNAL ;
    PORT
      LAYER M5 ;
        RECT 55.440 267.648 55.464 267.840 ;
    END
  END out_res[211]
  PIN out_res[212]
    DIRECTION OUTPUT ;
    USE SIGNAL ;
    PORT
      LAYER M5 ;
        RECT 55.680 267.648 55.704 267.840 ;
    END
  END out_res[212]
  PIN out_res[213]
    DIRECTION OUTPUT ;
    USE SIGNAL ;
    PORT
      LAYER M5 ;
        RECT 55.920 267.648 55.944 267.840 ;
    END
  END out_res[213]
  PIN out_res[214]
    DIRECTION OUTPUT ;
    USE SIGNAL ;
    PORT
      LAYER M5 ;
        RECT 56.160 267.648 56.184 267.840 ;
    END
  END out_res[214]
  PIN out_res[215]
    DIRECTION OUTPUT ;
    USE SIGNAL ;
    PORT
      LAYER M5 ;
        RECT 56.400 267.648 56.424 267.840 ;
    END
  END out_res[215]
  PIN out_res[216]
    DIRECTION OUTPUT ;
    USE SIGNAL ;
    PORT
      LAYER M5 ;
        RECT 56.640 267.648 56.664 267.840 ;
    END
  END out_res[216]
  PIN out_res[217]
    DIRECTION OUTPUT ;
    USE SIGNAL ;
    PORT
      LAYER M5 ;
        RECT 56.880 267.648 56.904 267.840 ;
    END
  END out_res[217]
  PIN out_res[218]
    DIRECTION OUTPUT ;
    USE SIGNAL ;
    PORT
      LAYER M5 ;
        RECT 57.120 267.648 57.144 267.840 ;
    END
  END out_res[218]
  PIN out_res[219]
    DIRECTION OUTPUT ;
    USE SIGNAL ;
    PORT
      LAYER M5 ;
        RECT 57.360 267.648 57.384 267.840 ;
    END
  END out_res[219]
  PIN out_res[220]
    DIRECTION OUTPUT ;
    USE SIGNAL ;
    PORT
      LAYER M5 ;
        RECT 57.600 267.648 57.624 267.840 ;
    END
  END out_res[220]
  PIN out_res[221]
    DIRECTION OUTPUT ;
    USE SIGNAL ;
    PORT
      LAYER M5 ;
        RECT 57.840 267.648 57.864 267.840 ;
    END
  END out_res[221]
  PIN out_res[222]
    DIRECTION OUTPUT ;
    USE SIGNAL ;
    PORT
      LAYER M5 ;
        RECT 58.080 267.648 58.104 267.840 ;
    END
  END out_res[222]
  PIN out_res[223]
    DIRECTION OUTPUT ;
    USE SIGNAL ;
    PORT
      LAYER M5 ;
        RECT 58.320 267.648 58.344 267.840 ;
    END
  END out_res[223]
  PIN out_res[224]
    DIRECTION OUTPUT ;
    USE SIGNAL ;
    PORT
      LAYER M5 ;
        RECT 58.560 267.648 58.584 267.840 ;
    END
  END out_res[224]
  PIN out_res[225]
    DIRECTION OUTPUT ;
    USE SIGNAL ;
    PORT
      LAYER M5 ;
        RECT 58.800 267.648 58.824 267.840 ;
    END
  END out_res[225]
  PIN out_res[226]
    DIRECTION OUTPUT ;
    USE SIGNAL ;
    PORT
      LAYER M5 ;
        RECT 59.040 267.648 59.064 267.840 ;
    END
  END out_res[226]
  PIN out_res[227]
    DIRECTION OUTPUT ;
    USE SIGNAL ;
    PORT
      LAYER M5 ;
        RECT 59.280 267.648 59.304 267.840 ;
    END
  END out_res[227]
  PIN out_res[228]
    DIRECTION OUTPUT ;
    USE SIGNAL ;
    PORT
      LAYER M5 ;
        RECT 59.520 267.648 59.544 267.840 ;
    END
  END out_res[228]
  PIN out_res[229]
    DIRECTION OUTPUT ;
    USE SIGNAL ;
    PORT
      LAYER M5 ;
        RECT 59.760 267.648 59.784 267.840 ;
    END
  END out_res[229]
  PIN out_res[230]
    DIRECTION OUTPUT ;
    USE SIGNAL ;
    PORT
      LAYER M5 ;
        RECT 60.000 267.648 60.024 267.840 ;
    END
  END out_res[230]
  PIN out_res[231]
    DIRECTION OUTPUT ;
    USE SIGNAL ;
    PORT
      LAYER M5 ;
        RECT 60.240 267.648 60.264 267.840 ;
    END
  END out_res[231]
  PIN out_res[232]
    DIRECTION OUTPUT ;
    USE SIGNAL ;
    PORT
      LAYER M5 ;
        RECT 60.480 267.648 60.504 267.840 ;
    END
  END out_res[232]
  PIN out_res[233]
    DIRECTION OUTPUT ;
    USE SIGNAL ;
    PORT
      LAYER M5 ;
        RECT 60.720 267.648 60.744 267.840 ;
    END
  END out_res[233]
  PIN out_res[234]
    DIRECTION OUTPUT ;
    USE SIGNAL ;
    PORT
      LAYER M5 ;
        RECT 60.960 267.648 60.984 267.840 ;
    END
  END out_res[234]
  PIN out_res[235]
    DIRECTION OUTPUT ;
    USE SIGNAL ;
    PORT
      LAYER M5 ;
        RECT 61.200 267.648 61.224 267.840 ;
    END
  END out_res[235]
  PIN out_res[236]
    DIRECTION OUTPUT ;
    USE SIGNAL ;
    PORT
      LAYER M5 ;
        RECT 61.440 267.648 61.464 267.840 ;
    END
  END out_res[236]
  PIN out_res[237]
    DIRECTION OUTPUT ;
    USE SIGNAL ;
    PORT
      LAYER M5 ;
        RECT 61.680 267.648 61.704 267.840 ;
    END
  END out_res[237]
  PIN out_res[238]
    DIRECTION OUTPUT ;
    USE SIGNAL ;
    PORT
      LAYER M5 ;
        RECT 61.920 267.648 61.944 267.840 ;
    END
  END out_res[238]
  PIN out_res[239]
    DIRECTION OUTPUT ;
    USE SIGNAL ;
    PORT
      LAYER M5 ;
        RECT 62.160 267.648 62.184 267.840 ;
    END
  END out_res[239]
  PIN out_res[240]
    DIRECTION OUTPUT ;
    USE SIGNAL ;
    PORT
      LAYER M5 ;
        RECT 62.400 267.648 62.424 267.840 ;
    END
  END out_res[240]
  PIN out_res[241]
    DIRECTION OUTPUT ;
    USE SIGNAL ;
    PORT
      LAYER M5 ;
        RECT 62.640 267.648 62.664 267.840 ;
    END
  END out_res[241]
  PIN out_res[242]
    DIRECTION OUTPUT ;
    USE SIGNAL ;
    PORT
      LAYER M5 ;
        RECT 62.880 267.648 62.904 267.840 ;
    END
  END out_res[242]
  PIN out_res[243]
    DIRECTION OUTPUT ;
    USE SIGNAL ;
    PORT
      LAYER M5 ;
        RECT 63.120 267.648 63.144 267.840 ;
    END
  END out_res[243]
  PIN out_res[244]
    DIRECTION OUTPUT ;
    USE SIGNAL ;
    PORT
      LAYER M5 ;
        RECT 63.360 267.648 63.384 267.840 ;
    END
  END out_res[244]
  PIN out_res[245]
    DIRECTION OUTPUT ;
    USE SIGNAL ;
    PORT
      LAYER M5 ;
        RECT 63.600 267.648 63.624 267.840 ;
    END
  END out_res[245]
  PIN out_res[246]
    DIRECTION OUTPUT ;
    USE SIGNAL ;
    PORT
      LAYER M5 ;
        RECT 63.840 267.648 63.864 267.840 ;
    END
  END out_res[246]
  PIN out_res[247]
    DIRECTION OUTPUT ;
    USE SIGNAL ;
    PORT
      LAYER M5 ;
        RECT 64.080 267.648 64.104 267.840 ;
    END
  END out_res[247]
  PIN out_res[248]
    DIRECTION OUTPUT ;
    USE SIGNAL ;
    PORT
      LAYER M5 ;
        RECT 64.320 267.648 64.344 267.840 ;
    END
  END out_res[248]
  PIN out_res[249]
    DIRECTION OUTPUT ;
    USE SIGNAL ;
    PORT
      LAYER M5 ;
        RECT 64.560 267.648 64.584 267.840 ;
    END
  END out_res[249]
  PIN out_res[250]
    DIRECTION OUTPUT ;
    USE SIGNAL ;
    PORT
      LAYER M5 ;
        RECT 64.800 267.648 64.824 267.840 ;
    END
  END out_res[250]
  PIN out_res[251]
    DIRECTION OUTPUT ;
    USE SIGNAL ;
    PORT
      LAYER M5 ;
        RECT 65.040 267.648 65.064 267.840 ;
    END
  END out_res[251]
  PIN out_res[252]
    DIRECTION OUTPUT ;
    USE SIGNAL ;
    PORT
      LAYER M5 ;
        RECT 65.280 267.648 65.304 267.840 ;
    END
  END out_res[252]
  PIN out_res[253]
    DIRECTION OUTPUT ;
    USE SIGNAL ;
    PORT
      LAYER M5 ;
        RECT 65.520 267.648 65.544 267.840 ;
    END
  END out_res[253]
  PIN out_res[254]
    DIRECTION OUTPUT ;
    USE SIGNAL ;
    PORT
      LAYER M5 ;
        RECT 65.760 267.648 65.784 267.840 ;
    END
  END out_res[254]
  PIN out_res[255]
    DIRECTION OUTPUT ;
    USE SIGNAL ;
    PORT
      LAYER M5 ;
        RECT 66.000 267.648 66.024 267.840 ;
    END
  END out_res[255]
  PIN out_res[256]
    DIRECTION OUTPUT ;
    USE SIGNAL ;
    PORT
      LAYER M5 ;
        RECT 66.240 267.648 66.264 267.840 ;
    END
  END out_res[256]
  PIN out_res[257]
    DIRECTION OUTPUT ;
    USE SIGNAL ;
    PORT
      LAYER M5 ;
        RECT 66.480 267.648 66.504 267.840 ;
    END
  END out_res[257]
  PIN out_res[258]
    DIRECTION OUTPUT ;
    USE SIGNAL ;
    PORT
      LAYER M5 ;
        RECT 66.720 267.648 66.744 267.840 ;
    END
  END out_res[258]
  PIN out_res[259]
    DIRECTION OUTPUT ;
    USE SIGNAL ;
    PORT
      LAYER M5 ;
        RECT 66.960 267.648 66.984 267.840 ;
    END
  END out_res[259]
  PIN out_res[260]
    DIRECTION OUTPUT ;
    USE SIGNAL ;
    PORT
      LAYER M5 ;
        RECT 67.200 267.648 67.224 267.840 ;
    END
  END out_res[260]
  PIN out_res[261]
    DIRECTION OUTPUT ;
    USE SIGNAL ;
    PORT
      LAYER M5 ;
        RECT 67.440 267.648 67.464 267.840 ;
    END
  END out_res[261]
  PIN out_res[262]
    DIRECTION OUTPUT ;
    USE SIGNAL ;
    PORT
      LAYER M5 ;
        RECT 67.680 267.648 67.704 267.840 ;
    END
  END out_res[262]
  PIN out_res[263]
    DIRECTION OUTPUT ;
    USE SIGNAL ;
    PORT
      LAYER M5 ;
        RECT 67.920 267.648 67.944 267.840 ;
    END
  END out_res[263]
  PIN out_res[264]
    DIRECTION OUTPUT ;
    USE SIGNAL ;
    PORT
      LAYER M5 ;
        RECT 68.160 267.648 68.184 267.840 ;
    END
  END out_res[264]
  PIN out_res[265]
    DIRECTION OUTPUT ;
    USE SIGNAL ;
    PORT
      LAYER M5 ;
        RECT 68.400 267.648 68.424 267.840 ;
    END
  END out_res[265]
  PIN out_res[266]
    DIRECTION OUTPUT ;
    USE SIGNAL ;
    PORT
      LAYER M5 ;
        RECT 68.640 267.648 68.664 267.840 ;
    END
  END out_res[266]
  PIN out_res[267]
    DIRECTION OUTPUT ;
    USE SIGNAL ;
    PORT
      LAYER M5 ;
        RECT 68.880 267.648 68.904 267.840 ;
    END
  END out_res[267]
  PIN out_res[268]
    DIRECTION OUTPUT ;
    USE SIGNAL ;
    PORT
      LAYER M5 ;
        RECT 69.120 267.648 69.144 267.840 ;
    END
  END out_res[268]
  PIN out_res[269]
    DIRECTION OUTPUT ;
    USE SIGNAL ;
    PORT
      LAYER M5 ;
        RECT 69.360 267.648 69.384 267.840 ;
    END
  END out_res[269]
  PIN out_res[270]
    DIRECTION OUTPUT ;
    USE SIGNAL ;
    PORT
      LAYER M5 ;
        RECT 69.600 267.648 69.624 267.840 ;
    END
  END out_res[270]
  PIN out_res[271]
    DIRECTION OUTPUT ;
    USE SIGNAL ;
    PORT
      LAYER M5 ;
        RECT 69.840 267.648 69.864 267.840 ;
    END
  END out_res[271]
  PIN out_res[272]
    DIRECTION OUTPUT ;
    USE SIGNAL ;
    PORT
      LAYER M5 ;
        RECT 70.080 267.648 70.104 267.840 ;
    END
  END out_res[272]
  PIN out_res[273]
    DIRECTION OUTPUT ;
    USE SIGNAL ;
    PORT
      LAYER M5 ;
        RECT 70.320 267.648 70.344 267.840 ;
    END
  END out_res[273]
  PIN out_res[274]
    DIRECTION OUTPUT ;
    USE SIGNAL ;
    PORT
      LAYER M5 ;
        RECT 70.560 267.648 70.584 267.840 ;
    END
  END out_res[274]
  PIN out_res[275]
    DIRECTION OUTPUT ;
    USE SIGNAL ;
    PORT
      LAYER M5 ;
        RECT 70.800 267.648 70.824 267.840 ;
    END
  END out_res[275]
  PIN out_res[276]
    DIRECTION OUTPUT ;
    USE SIGNAL ;
    PORT
      LAYER M5 ;
        RECT 71.040 267.648 71.064 267.840 ;
    END
  END out_res[276]
  PIN out_res[277]
    DIRECTION OUTPUT ;
    USE SIGNAL ;
    PORT
      LAYER M5 ;
        RECT 71.280 267.648 71.304 267.840 ;
    END
  END out_res[277]
  PIN out_res[278]
    DIRECTION OUTPUT ;
    USE SIGNAL ;
    PORT
      LAYER M5 ;
        RECT 71.520 267.648 71.544 267.840 ;
    END
  END out_res[278]
  PIN out_res[279]
    DIRECTION OUTPUT ;
    USE SIGNAL ;
    PORT
      LAYER M5 ;
        RECT 71.760 267.648 71.784 267.840 ;
    END
  END out_res[279]
  PIN out_res[280]
    DIRECTION OUTPUT ;
    USE SIGNAL ;
    PORT
      LAYER M5 ;
        RECT 72.000 267.648 72.024 267.840 ;
    END
  END out_res[280]
  PIN out_res[281]
    DIRECTION OUTPUT ;
    USE SIGNAL ;
    PORT
      LAYER M5 ;
        RECT 72.240 267.648 72.264 267.840 ;
    END
  END out_res[281]
  PIN out_res[282]
    DIRECTION OUTPUT ;
    USE SIGNAL ;
    PORT
      LAYER M5 ;
        RECT 72.480 267.648 72.504 267.840 ;
    END
  END out_res[282]
  PIN out_res[283]
    DIRECTION OUTPUT ;
    USE SIGNAL ;
    PORT
      LAYER M5 ;
        RECT 72.720 267.648 72.744 267.840 ;
    END
  END out_res[283]
  PIN out_res[284]
    DIRECTION OUTPUT ;
    USE SIGNAL ;
    PORT
      LAYER M5 ;
        RECT 72.960 267.648 72.984 267.840 ;
    END
  END out_res[284]
  PIN out_res[285]
    DIRECTION OUTPUT ;
    USE SIGNAL ;
    PORT
      LAYER M5 ;
        RECT 73.200 267.648 73.224 267.840 ;
    END
  END out_res[285]
  PIN out_res[286]
    DIRECTION OUTPUT ;
    USE SIGNAL ;
    PORT
      LAYER M5 ;
        RECT 73.440 267.648 73.464 267.840 ;
    END
  END out_res[286]
  PIN out_res[287]
    DIRECTION OUTPUT ;
    USE SIGNAL ;
    PORT
      LAYER M5 ;
        RECT 73.680 267.648 73.704 267.840 ;
    END
  END out_res[287]
  PIN out_res[288]
    DIRECTION OUTPUT ;
    USE SIGNAL ;
    PORT
      LAYER M5 ;
        RECT 73.920 267.648 73.944 267.840 ;
    END
  END out_res[288]
  PIN out_res[289]
    DIRECTION OUTPUT ;
    USE SIGNAL ;
    PORT
      LAYER M5 ;
        RECT 74.160 267.648 74.184 267.840 ;
    END
  END out_res[289]
  PIN out_res[290]
    DIRECTION OUTPUT ;
    USE SIGNAL ;
    PORT
      LAYER M5 ;
        RECT 74.400 267.648 74.424 267.840 ;
    END
  END out_res[290]
  PIN out_res[291]
    DIRECTION OUTPUT ;
    USE SIGNAL ;
    PORT
      LAYER M5 ;
        RECT 74.640 267.648 74.664 267.840 ;
    END
  END out_res[291]
  PIN out_res[292]
    DIRECTION OUTPUT ;
    USE SIGNAL ;
    PORT
      LAYER M5 ;
        RECT 74.880 267.648 74.904 267.840 ;
    END
  END out_res[292]
  PIN out_res[293]
    DIRECTION OUTPUT ;
    USE SIGNAL ;
    PORT
      LAYER M5 ;
        RECT 75.120 267.648 75.144 267.840 ;
    END
  END out_res[293]
  PIN out_res[294]
    DIRECTION OUTPUT ;
    USE SIGNAL ;
    PORT
      LAYER M5 ;
        RECT 75.360 267.648 75.384 267.840 ;
    END
  END out_res[294]
  PIN out_res[295]
    DIRECTION OUTPUT ;
    USE SIGNAL ;
    PORT
      LAYER M5 ;
        RECT 75.600 267.648 75.624 267.840 ;
    END
  END out_res[295]
  PIN out_res[296]
    DIRECTION OUTPUT ;
    USE SIGNAL ;
    PORT
      LAYER M5 ;
        RECT 75.840 267.648 75.864 267.840 ;
    END
  END out_res[296]
  PIN out_res[297]
    DIRECTION OUTPUT ;
    USE SIGNAL ;
    PORT
      LAYER M5 ;
        RECT 76.080 267.648 76.104 267.840 ;
    END
  END out_res[297]
  PIN out_res[298]
    DIRECTION OUTPUT ;
    USE SIGNAL ;
    PORT
      LAYER M5 ;
        RECT 76.320 267.648 76.344 267.840 ;
    END
  END out_res[298]
  PIN out_res[299]
    DIRECTION OUTPUT ;
    USE SIGNAL ;
    PORT
      LAYER M5 ;
        RECT 76.560 267.648 76.584 267.840 ;
    END
  END out_res[299]
  PIN out_res[300]
    DIRECTION OUTPUT ;
    USE SIGNAL ;
    PORT
      LAYER M5 ;
        RECT 76.800 267.648 76.824 267.840 ;
    END
  END out_res[300]
  PIN out_res[301]
    DIRECTION OUTPUT ;
    USE SIGNAL ;
    PORT
      LAYER M5 ;
        RECT 77.040 267.648 77.064 267.840 ;
    END
  END out_res[301]
  PIN out_res[302]
    DIRECTION OUTPUT ;
    USE SIGNAL ;
    PORT
      LAYER M5 ;
        RECT 77.280 267.648 77.304 267.840 ;
    END
  END out_res[302]
  PIN out_res[303]
    DIRECTION OUTPUT ;
    USE SIGNAL ;
    PORT
      LAYER M5 ;
        RECT 77.520 267.648 77.544 267.840 ;
    END
  END out_res[303]
  PIN out_res[304]
    DIRECTION OUTPUT ;
    USE SIGNAL ;
    PORT
      LAYER M5 ;
        RECT 77.760 267.648 77.784 267.840 ;
    END
  END out_res[304]
  PIN out_res[305]
    DIRECTION OUTPUT ;
    USE SIGNAL ;
    PORT
      LAYER M5 ;
        RECT 78.000 267.648 78.024 267.840 ;
    END
  END out_res[305]
  PIN out_res[306]
    DIRECTION OUTPUT ;
    USE SIGNAL ;
    PORT
      LAYER M5 ;
        RECT 78.240 267.648 78.264 267.840 ;
    END
  END out_res[306]
  PIN out_res[307]
    DIRECTION OUTPUT ;
    USE SIGNAL ;
    PORT
      LAYER M5 ;
        RECT 78.480 267.648 78.504 267.840 ;
    END
  END out_res[307]
  PIN out_res[308]
    DIRECTION OUTPUT ;
    USE SIGNAL ;
    PORT
      LAYER M5 ;
        RECT 78.720 267.648 78.744 267.840 ;
    END
  END out_res[308]
  PIN out_res[309]
    DIRECTION OUTPUT ;
    USE SIGNAL ;
    PORT
      LAYER M5 ;
        RECT 78.960 267.648 78.984 267.840 ;
    END
  END out_res[309]
  PIN out_res[310]
    DIRECTION OUTPUT ;
    USE SIGNAL ;
    PORT
      LAYER M5 ;
        RECT 79.200 267.648 79.224 267.840 ;
    END
  END out_res[310]
  PIN out_res[311]
    DIRECTION OUTPUT ;
    USE SIGNAL ;
    PORT
      LAYER M5 ;
        RECT 79.440 267.648 79.464 267.840 ;
    END
  END out_res[311]
  PIN out_res[312]
    DIRECTION OUTPUT ;
    USE SIGNAL ;
    PORT
      LAYER M5 ;
        RECT 79.680 267.648 79.704 267.840 ;
    END
  END out_res[312]
  PIN out_res[313]
    DIRECTION OUTPUT ;
    USE SIGNAL ;
    PORT
      LAYER M5 ;
        RECT 79.920 267.648 79.944 267.840 ;
    END
  END out_res[313]
  PIN out_res[314]
    DIRECTION OUTPUT ;
    USE SIGNAL ;
    PORT
      LAYER M5 ;
        RECT 80.160 267.648 80.184 267.840 ;
    END
  END out_res[314]
  PIN out_res[315]
    DIRECTION OUTPUT ;
    USE SIGNAL ;
    PORT
      LAYER M5 ;
        RECT 80.400 267.648 80.424 267.840 ;
    END
  END out_res[315]
  PIN out_res[316]
    DIRECTION OUTPUT ;
    USE SIGNAL ;
    PORT
      LAYER M5 ;
        RECT 80.640 267.648 80.664 267.840 ;
    END
  END out_res[316]
  PIN out_res[317]
    DIRECTION OUTPUT ;
    USE SIGNAL ;
    PORT
      LAYER M5 ;
        RECT 80.880 267.648 80.904 267.840 ;
    END
  END out_res[317]
  PIN out_res[318]
    DIRECTION OUTPUT ;
    USE SIGNAL ;
    PORT
      LAYER M5 ;
        RECT 81.120 267.648 81.144 267.840 ;
    END
  END out_res[318]
  PIN out_res[319]
    DIRECTION OUTPUT ;
    USE SIGNAL ;
    PORT
      LAYER M5 ;
        RECT 81.360 267.648 81.384 267.840 ;
    END
  END out_res[319]
  PIN out_res[320]
    DIRECTION OUTPUT ;
    USE SIGNAL ;
    PORT
      LAYER M5 ;
        RECT 81.600 267.648 81.624 267.840 ;
    END
  END out_res[320]
  PIN out_res[321]
    DIRECTION OUTPUT ;
    USE SIGNAL ;
    PORT
      LAYER M5 ;
        RECT 81.840 267.648 81.864 267.840 ;
    END
  END out_res[321]
  PIN out_res[322]
    DIRECTION OUTPUT ;
    USE SIGNAL ;
    PORT
      LAYER M5 ;
        RECT 82.080 267.648 82.104 267.840 ;
    END
  END out_res[322]
  PIN out_res[323]
    DIRECTION OUTPUT ;
    USE SIGNAL ;
    PORT
      LAYER M5 ;
        RECT 82.320 267.648 82.344 267.840 ;
    END
  END out_res[323]
  PIN out_res[324]
    DIRECTION OUTPUT ;
    USE SIGNAL ;
    PORT
      LAYER M5 ;
        RECT 82.560 267.648 82.584 267.840 ;
    END
  END out_res[324]
  PIN out_res[325]
    DIRECTION OUTPUT ;
    USE SIGNAL ;
    PORT
      LAYER M5 ;
        RECT 82.800 267.648 82.824 267.840 ;
    END
  END out_res[325]
  PIN out_res[326]
    DIRECTION OUTPUT ;
    USE SIGNAL ;
    PORT
      LAYER M5 ;
        RECT 83.040 267.648 83.064 267.840 ;
    END
  END out_res[326]
  PIN out_res[327]
    DIRECTION OUTPUT ;
    USE SIGNAL ;
    PORT
      LAYER M5 ;
        RECT 83.280 267.648 83.304 267.840 ;
    END
  END out_res[327]
  PIN out_res[328]
    DIRECTION OUTPUT ;
    USE SIGNAL ;
    PORT
      LAYER M5 ;
        RECT 83.520 267.648 83.544 267.840 ;
    END
  END out_res[328]
  PIN out_res[329]
    DIRECTION OUTPUT ;
    USE SIGNAL ;
    PORT
      LAYER M5 ;
        RECT 83.760 267.648 83.784 267.840 ;
    END
  END out_res[329]
  PIN out_res[330]
    DIRECTION OUTPUT ;
    USE SIGNAL ;
    PORT
      LAYER M5 ;
        RECT 84.000 267.648 84.024 267.840 ;
    END
  END out_res[330]
  PIN out_res[331]
    DIRECTION OUTPUT ;
    USE SIGNAL ;
    PORT
      LAYER M5 ;
        RECT 84.240 267.648 84.264 267.840 ;
    END
  END out_res[331]
  PIN out_res[332]
    DIRECTION OUTPUT ;
    USE SIGNAL ;
    PORT
      LAYER M5 ;
        RECT 84.480 267.648 84.504 267.840 ;
    END
  END out_res[332]
  PIN out_res[333]
    DIRECTION OUTPUT ;
    USE SIGNAL ;
    PORT
      LAYER M5 ;
        RECT 84.720 267.648 84.744 267.840 ;
    END
  END out_res[333]
  PIN out_res[334]
    DIRECTION OUTPUT ;
    USE SIGNAL ;
    PORT
      LAYER M5 ;
        RECT 84.960 267.648 84.984 267.840 ;
    END
  END out_res[334]
  PIN out_res[335]
    DIRECTION OUTPUT ;
    USE SIGNAL ;
    PORT
      LAYER M5 ;
        RECT 85.200 267.648 85.224 267.840 ;
    END
  END out_res[335]
  PIN out_res[336]
    DIRECTION OUTPUT ;
    USE SIGNAL ;
    PORT
      LAYER M5 ;
        RECT 85.440 267.648 85.464 267.840 ;
    END
  END out_res[336]
  PIN out_res[337]
    DIRECTION OUTPUT ;
    USE SIGNAL ;
    PORT
      LAYER M5 ;
        RECT 85.680 267.648 85.704 267.840 ;
    END
  END out_res[337]
  PIN out_res[338]
    DIRECTION OUTPUT ;
    USE SIGNAL ;
    PORT
      LAYER M5 ;
        RECT 85.920 267.648 85.944 267.840 ;
    END
  END out_res[338]
  PIN out_res[339]
    DIRECTION OUTPUT ;
    USE SIGNAL ;
    PORT
      LAYER M5 ;
        RECT 86.160 267.648 86.184 267.840 ;
    END
  END out_res[339]
  PIN out_res[340]
    DIRECTION OUTPUT ;
    USE SIGNAL ;
    PORT
      LAYER M5 ;
        RECT 86.400 267.648 86.424 267.840 ;
    END
  END out_res[340]
  PIN out_res[341]
    DIRECTION OUTPUT ;
    USE SIGNAL ;
    PORT
      LAYER M5 ;
        RECT 86.640 267.648 86.664 267.840 ;
    END
  END out_res[341]
  PIN out_res[342]
    DIRECTION OUTPUT ;
    USE SIGNAL ;
    PORT
      LAYER M5 ;
        RECT 86.880 267.648 86.904 267.840 ;
    END
  END out_res[342]
  PIN out_res[343]
    DIRECTION OUTPUT ;
    USE SIGNAL ;
    PORT
      LAYER M5 ;
        RECT 87.120 267.648 87.144 267.840 ;
    END
  END out_res[343]
  PIN out_res[344]
    DIRECTION OUTPUT ;
    USE SIGNAL ;
    PORT
      LAYER M5 ;
        RECT 87.360 267.648 87.384 267.840 ;
    END
  END out_res[344]
  PIN out_res[345]
    DIRECTION OUTPUT ;
    USE SIGNAL ;
    PORT
      LAYER M5 ;
        RECT 87.600 267.648 87.624 267.840 ;
    END
  END out_res[345]
  PIN out_res[346]
    DIRECTION OUTPUT ;
    USE SIGNAL ;
    PORT
      LAYER M5 ;
        RECT 87.840 267.648 87.864 267.840 ;
    END
  END out_res[346]
  PIN out_res[347]
    DIRECTION OUTPUT ;
    USE SIGNAL ;
    PORT
      LAYER M5 ;
        RECT 88.080 267.648 88.104 267.840 ;
    END
  END out_res[347]
  PIN out_res[348]
    DIRECTION OUTPUT ;
    USE SIGNAL ;
    PORT
      LAYER M5 ;
        RECT 88.320 267.648 88.344 267.840 ;
    END
  END out_res[348]
  PIN out_res[349]
    DIRECTION OUTPUT ;
    USE SIGNAL ;
    PORT
      LAYER M5 ;
        RECT 88.560 267.648 88.584 267.840 ;
    END
  END out_res[349]
  PIN out_res[350]
    DIRECTION OUTPUT ;
    USE SIGNAL ;
    PORT
      LAYER M5 ;
        RECT 88.800 267.648 88.824 267.840 ;
    END
  END out_res[350]
  PIN out_res[351]
    DIRECTION OUTPUT ;
    USE SIGNAL ;
    PORT
      LAYER M5 ;
        RECT 89.040 267.648 89.064 267.840 ;
    END
  END out_res[351]
  PIN out_res[352]
    DIRECTION OUTPUT ;
    USE SIGNAL ;
    PORT
      LAYER M5 ;
        RECT 89.280 267.648 89.304 267.840 ;
    END
  END out_res[352]
  PIN out_res[353]
    DIRECTION OUTPUT ;
    USE SIGNAL ;
    PORT
      LAYER M5 ;
        RECT 89.520 267.648 89.544 267.840 ;
    END
  END out_res[353]
  PIN out_res[354]
    DIRECTION OUTPUT ;
    USE SIGNAL ;
    PORT
      LAYER M5 ;
        RECT 89.760 267.648 89.784 267.840 ;
    END
  END out_res[354]
  PIN out_res[355]
    DIRECTION OUTPUT ;
    USE SIGNAL ;
    PORT
      LAYER M5 ;
        RECT 90.000 267.648 90.024 267.840 ;
    END
  END out_res[355]
  PIN out_res[356]
    DIRECTION OUTPUT ;
    USE SIGNAL ;
    PORT
      LAYER M5 ;
        RECT 90.240 267.648 90.264 267.840 ;
    END
  END out_res[356]
  PIN out_res[357]
    DIRECTION OUTPUT ;
    USE SIGNAL ;
    PORT
      LAYER M5 ;
        RECT 90.480 267.648 90.504 267.840 ;
    END
  END out_res[357]
  PIN out_res[358]
    DIRECTION OUTPUT ;
    USE SIGNAL ;
    PORT
      LAYER M5 ;
        RECT 90.720 267.648 90.744 267.840 ;
    END
  END out_res[358]
  PIN out_res[359]
    DIRECTION OUTPUT ;
    USE SIGNAL ;
    PORT
      LAYER M5 ;
        RECT 90.960 267.648 90.984 267.840 ;
    END
  END out_res[359]
  PIN out_res[360]
    DIRECTION OUTPUT ;
    USE SIGNAL ;
    PORT
      LAYER M5 ;
        RECT 91.200 267.648 91.224 267.840 ;
    END
  END out_res[360]
  PIN out_res[361]
    DIRECTION OUTPUT ;
    USE SIGNAL ;
    PORT
      LAYER M5 ;
        RECT 91.440 267.648 91.464 267.840 ;
    END
  END out_res[361]
  PIN out_res[362]
    DIRECTION OUTPUT ;
    USE SIGNAL ;
    PORT
      LAYER M5 ;
        RECT 91.680 267.648 91.704 267.840 ;
    END
  END out_res[362]
  PIN out_res[363]
    DIRECTION OUTPUT ;
    USE SIGNAL ;
    PORT
      LAYER M5 ;
        RECT 91.920 267.648 91.944 267.840 ;
    END
  END out_res[363]
  PIN out_res[364]
    DIRECTION OUTPUT ;
    USE SIGNAL ;
    PORT
      LAYER M5 ;
        RECT 92.160 267.648 92.184 267.840 ;
    END
  END out_res[364]
  PIN out_res[365]
    DIRECTION OUTPUT ;
    USE SIGNAL ;
    PORT
      LAYER M5 ;
        RECT 92.400 267.648 92.424 267.840 ;
    END
  END out_res[365]
  PIN out_res[366]
    DIRECTION OUTPUT ;
    USE SIGNAL ;
    PORT
      LAYER M5 ;
        RECT 92.640 267.648 92.664 267.840 ;
    END
  END out_res[366]
  PIN out_res[367]
    DIRECTION OUTPUT ;
    USE SIGNAL ;
    PORT
      LAYER M5 ;
        RECT 92.880 267.648 92.904 267.840 ;
    END
  END out_res[367]
  PIN out_res[368]
    DIRECTION OUTPUT ;
    USE SIGNAL ;
    PORT
      LAYER M5 ;
        RECT 93.120 267.648 93.144 267.840 ;
    END
  END out_res[368]
  PIN out_res[369]
    DIRECTION OUTPUT ;
    USE SIGNAL ;
    PORT
      LAYER M5 ;
        RECT 93.360 267.648 93.384 267.840 ;
    END
  END out_res[369]
  PIN out_res[370]
    DIRECTION OUTPUT ;
    USE SIGNAL ;
    PORT
      LAYER M5 ;
        RECT 93.600 267.648 93.624 267.840 ;
    END
  END out_res[370]
  PIN out_res[371]
    DIRECTION OUTPUT ;
    USE SIGNAL ;
    PORT
      LAYER M5 ;
        RECT 93.840 267.648 93.864 267.840 ;
    END
  END out_res[371]
  PIN out_res[372]
    DIRECTION OUTPUT ;
    USE SIGNAL ;
    PORT
      LAYER M5 ;
        RECT 94.080 267.648 94.104 267.840 ;
    END
  END out_res[372]
  PIN out_res[373]
    DIRECTION OUTPUT ;
    USE SIGNAL ;
    PORT
      LAYER M5 ;
        RECT 94.320 267.648 94.344 267.840 ;
    END
  END out_res[373]
  PIN out_res[374]
    DIRECTION OUTPUT ;
    USE SIGNAL ;
    PORT
      LAYER M5 ;
        RECT 94.560 267.648 94.584 267.840 ;
    END
  END out_res[374]
  PIN out_res[375]
    DIRECTION OUTPUT ;
    USE SIGNAL ;
    PORT
      LAYER M5 ;
        RECT 94.800 267.648 94.824 267.840 ;
    END
  END out_res[375]
  PIN out_res[376]
    DIRECTION OUTPUT ;
    USE SIGNAL ;
    PORT
      LAYER M5 ;
        RECT 95.040 267.648 95.064 267.840 ;
    END
  END out_res[376]
  PIN out_res[377]
    DIRECTION OUTPUT ;
    USE SIGNAL ;
    PORT
      LAYER M5 ;
        RECT 95.280 267.648 95.304 267.840 ;
    END
  END out_res[377]
  PIN out_res[378]
    DIRECTION OUTPUT ;
    USE SIGNAL ;
    PORT
      LAYER M5 ;
        RECT 95.520 267.648 95.544 267.840 ;
    END
  END out_res[378]
  PIN out_res[379]
    DIRECTION OUTPUT ;
    USE SIGNAL ;
    PORT
      LAYER M5 ;
        RECT 95.760 267.648 95.784 267.840 ;
    END
  END out_res[379]
  PIN out_res[380]
    DIRECTION OUTPUT ;
    USE SIGNAL ;
    PORT
      LAYER M5 ;
        RECT 96.000 267.648 96.024 267.840 ;
    END
  END out_res[380]
  PIN out_res[381]
    DIRECTION OUTPUT ;
    USE SIGNAL ;
    PORT
      LAYER M5 ;
        RECT 96.240 267.648 96.264 267.840 ;
    END
  END out_res[381]
  PIN out_res[382]
    DIRECTION OUTPUT ;
    USE SIGNAL ;
    PORT
      LAYER M5 ;
        RECT 96.480 267.648 96.504 267.840 ;
    END
  END out_res[382]
  PIN out_res[383]
    DIRECTION OUTPUT ;
    USE SIGNAL ;
    PORT
      LAYER M5 ;
        RECT 96.720 267.648 96.744 267.840 ;
    END
  END out_res[383]
  PIN out_res[384]
    DIRECTION OUTPUT ;
    USE SIGNAL ;
    PORT
      LAYER M5 ;
        RECT 96.960 267.648 96.984 267.840 ;
    END
  END out_res[384]
  PIN out_res[385]
    DIRECTION OUTPUT ;
    USE SIGNAL ;
    PORT
      LAYER M5 ;
        RECT 97.200 267.648 97.224 267.840 ;
    END
  END out_res[385]
  PIN out_res[386]
    DIRECTION OUTPUT ;
    USE SIGNAL ;
    PORT
      LAYER M5 ;
        RECT 97.440 267.648 97.464 267.840 ;
    END
  END out_res[386]
  PIN out_res[387]
    DIRECTION OUTPUT ;
    USE SIGNAL ;
    PORT
      LAYER M5 ;
        RECT 97.680 267.648 97.704 267.840 ;
    END
  END out_res[387]
  PIN out_res[388]
    DIRECTION OUTPUT ;
    USE SIGNAL ;
    PORT
      LAYER M5 ;
        RECT 97.920 267.648 97.944 267.840 ;
    END
  END out_res[388]
  PIN out_res[389]
    DIRECTION OUTPUT ;
    USE SIGNAL ;
    PORT
      LAYER M5 ;
        RECT 98.160 267.648 98.184 267.840 ;
    END
  END out_res[389]
  PIN out_res[390]
    DIRECTION OUTPUT ;
    USE SIGNAL ;
    PORT
      LAYER M5 ;
        RECT 98.400 267.648 98.424 267.840 ;
    END
  END out_res[390]
  PIN out_res[391]
    DIRECTION OUTPUT ;
    USE SIGNAL ;
    PORT
      LAYER M5 ;
        RECT 98.640 267.648 98.664 267.840 ;
    END
  END out_res[391]
  PIN out_res[392]
    DIRECTION OUTPUT ;
    USE SIGNAL ;
    PORT
      LAYER M5 ;
        RECT 98.880 267.648 98.904 267.840 ;
    END
  END out_res[392]
  PIN out_res[393]
    DIRECTION OUTPUT ;
    USE SIGNAL ;
    PORT
      LAYER M5 ;
        RECT 99.120 267.648 99.144 267.840 ;
    END
  END out_res[393]
  PIN out_res[394]
    DIRECTION OUTPUT ;
    USE SIGNAL ;
    PORT
      LAYER M5 ;
        RECT 99.360 267.648 99.384 267.840 ;
    END
  END out_res[394]
  PIN out_res[395]
    DIRECTION OUTPUT ;
    USE SIGNAL ;
    PORT
      LAYER M5 ;
        RECT 99.600 267.648 99.624 267.840 ;
    END
  END out_res[395]
  PIN out_res[396]
    DIRECTION OUTPUT ;
    USE SIGNAL ;
    PORT
      LAYER M5 ;
        RECT 99.840 267.648 99.864 267.840 ;
    END
  END out_res[396]
  PIN out_res[397]
    DIRECTION OUTPUT ;
    USE SIGNAL ;
    PORT
      LAYER M5 ;
        RECT 100.080 267.648 100.104 267.840 ;
    END
  END out_res[397]
  PIN out_res[398]
    DIRECTION OUTPUT ;
    USE SIGNAL ;
    PORT
      LAYER M5 ;
        RECT 100.320 267.648 100.344 267.840 ;
    END
  END out_res[398]
  PIN out_res[399]
    DIRECTION OUTPUT ;
    USE SIGNAL ;
    PORT
      LAYER M5 ;
        RECT 100.560 267.648 100.584 267.840 ;
    END
  END out_res[399]
  PIN out_res[400]
    DIRECTION OUTPUT ;
    USE SIGNAL ;
    PORT
      LAYER M5 ;
        RECT 100.800 267.648 100.824 267.840 ;
    END
  END out_res[400]
  PIN out_res[401]
    DIRECTION OUTPUT ;
    USE SIGNAL ;
    PORT
      LAYER M5 ;
        RECT 101.040 267.648 101.064 267.840 ;
    END
  END out_res[401]
  PIN out_res[402]
    DIRECTION OUTPUT ;
    USE SIGNAL ;
    PORT
      LAYER M5 ;
        RECT 101.280 267.648 101.304 267.840 ;
    END
  END out_res[402]
  PIN out_res[403]
    DIRECTION OUTPUT ;
    USE SIGNAL ;
    PORT
      LAYER M5 ;
        RECT 101.520 267.648 101.544 267.840 ;
    END
  END out_res[403]
  PIN out_res[404]
    DIRECTION OUTPUT ;
    USE SIGNAL ;
    PORT
      LAYER M5 ;
        RECT 101.760 267.648 101.784 267.840 ;
    END
  END out_res[404]
  PIN out_res[405]
    DIRECTION OUTPUT ;
    USE SIGNAL ;
    PORT
      LAYER M5 ;
        RECT 102.000 267.648 102.024 267.840 ;
    END
  END out_res[405]
  PIN out_res[406]
    DIRECTION OUTPUT ;
    USE SIGNAL ;
    PORT
      LAYER M5 ;
        RECT 102.240 267.648 102.264 267.840 ;
    END
  END out_res[406]
  PIN out_res[407]
    DIRECTION OUTPUT ;
    USE SIGNAL ;
    PORT
      LAYER M5 ;
        RECT 102.480 267.648 102.504 267.840 ;
    END
  END out_res[407]
  PIN out_res[408]
    DIRECTION OUTPUT ;
    USE SIGNAL ;
    PORT
      LAYER M5 ;
        RECT 102.720 267.648 102.744 267.840 ;
    END
  END out_res[408]
  PIN out_res[409]
    DIRECTION OUTPUT ;
    USE SIGNAL ;
    PORT
      LAYER M5 ;
        RECT 102.960 267.648 102.984 267.840 ;
    END
  END out_res[409]
  PIN out_res[410]
    DIRECTION OUTPUT ;
    USE SIGNAL ;
    PORT
      LAYER M5 ;
        RECT 103.200 267.648 103.224 267.840 ;
    END
  END out_res[410]
  PIN out_res[411]
    DIRECTION OUTPUT ;
    USE SIGNAL ;
    PORT
      LAYER M5 ;
        RECT 103.440 267.648 103.464 267.840 ;
    END
  END out_res[411]
  PIN out_res[412]
    DIRECTION OUTPUT ;
    USE SIGNAL ;
    PORT
      LAYER M5 ;
        RECT 103.680 267.648 103.704 267.840 ;
    END
  END out_res[412]
  PIN out_res[413]
    DIRECTION OUTPUT ;
    USE SIGNAL ;
    PORT
      LAYER M5 ;
        RECT 103.920 267.648 103.944 267.840 ;
    END
  END out_res[413]
  PIN out_res[414]
    DIRECTION OUTPUT ;
    USE SIGNAL ;
    PORT
      LAYER M5 ;
        RECT 104.160 267.648 104.184 267.840 ;
    END
  END out_res[414]
  PIN out_res[415]
    DIRECTION OUTPUT ;
    USE SIGNAL ;
    PORT
      LAYER M5 ;
        RECT 104.400 267.648 104.424 267.840 ;
    END
  END out_res[415]
  PIN out_res[416]
    DIRECTION OUTPUT ;
    USE SIGNAL ;
    PORT
      LAYER M5 ;
        RECT 104.640 267.648 104.664 267.840 ;
    END
  END out_res[416]
  PIN out_res[417]
    DIRECTION OUTPUT ;
    USE SIGNAL ;
    PORT
      LAYER M5 ;
        RECT 104.880 267.648 104.904 267.840 ;
    END
  END out_res[417]
  PIN out_res[418]
    DIRECTION OUTPUT ;
    USE SIGNAL ;
    PORT
      LAYER M5 ;
        RECT 105.120 267.648 105.144 267.840 ;
    END
  END out_res[418]
  PIN out_res[419]
    DIRECTION OUTPUT ;
    USE SIGNAL ;
    PORT
      LAYER M5 ;
        RECT 105.360 267.648 105.384 267.840 ;
    END
  END out_res[419]
  PIN out_res[420]
    DIRECTION OUTPUT ;
    USE SIGNAL ;
    PORT
      LAYER M5 ;
        RECT 105.600 267.648 105.624 267.840 ;
    END
  END out_res[420]
  PIN out_res[421]
    DIRECTION OUTPUT ;
    USE SIGNAL ;
    PORT
      LAYER M5 ;
        RECT 105.840 267.648 105.864 267.840 ;
    END
  END out_res[421]
  PIN out_res[422]
    DIRECTION OUTPUT ;
    USE SIGNAL ;
    PORT
      LAYER M5 ;
        RECT 106.080 267.648 106.104 267.840 ;
    END
  END out_res[422]
  PIN out_res[423]
    DIRECTION OUTPUT ;
    USE SIGNAL ;
    PORT
      LAYER M5 ;
        RECT 106.320 267.648 106.344 267.840 ;
    END
  END out_res[423]
  PIN out_res[424]
    DIRECTION OUTPUT ;
    USE SIGNAL ;
    PORT
      LAYER M5 ;
        RECT 106.560 267.648 106.584 267.840 ;
    END
  END out_res[424]
  PIN out_res[425]
    DIRECTION OUTPUT ;
    USE SIGNAL ;
    PORT
      LAYER M5 ;
        RECT 106.800 267.648 106.824 267.840 ;
    END
  END out_res[425]
  PIN out_res[426]
    DIRECTION OUTPUT ;
    USE SIGNAL ;
    PORT
      LAYER M5 ;
        RECT 107.040 267.648 107.064 267.840 ;
    END
  END out_res[426]
  PIN out_res[427]
    DIRECTION OUTPUT ;
    USE SIGNAL ;
    PORT
      LAYER M5 ;
        RECT 107.280 267.648 107.304 267.840 ;
    END
  END out_res[427]
  PIN out_res[428]
    DIRECTION OUTPUT ;
    USE SIGNAL ;
    PORT
      LAYER M5 ;
        RECT 107.520 267.648 107.544 267.840 ;
    END
  END out_res[428]
  PIN out_res[429]
    DIRECTION OUTPUT ;
    USE SIGNAL ;
    PORT
      LAYER M5 ;
        RECT 107.760 267.648 107.784 267.840 ;
    END
  END out_res[429]
  PIN out_res[430]
    DIRECTION OUTPUT ;
    USE SIGNAL ;
    PORT
      LAYER M5 ;
        RECT 108.000 267.648 108.024 267.840 ;
    END
  END out_res[430]
  PIN out_res[431]
    DIRECTION OUTPUT ;
    USE SIGNAL ;
    PORT
      LAYER M5 ;
        RECT 108.240 267.648 108.264 267.840 ;
    END
  END out_res[431]
  PIN out_res[432]
    DIRECTION OUTPUT ;
    USE SIGNAL ;
    PORT
      LAYER M5 ;
        RECT 108.480 267.648 108.504 267.840 ;
    END
  END out_res[432]
  PIN out_res[433]
    DIRECTION OUTPUT ;
    USE SIGNAL ;
    PORT
      LAYER M5 ;
        RECT 108.720 267.648 108.744 267.840 ;
    END
  END out_res[433]
  PIN out_res[434]
    DIRECTION OUTPUT ;
    USE SIGNAL ;
    PORT
      LAYER M5 ;
        RECT 108.960 267.648 108.984 267.840 ;
    END
  END out_res[434]
  PIN out_res[435]
    DIRECTION OUTPUT ;
    USE SIGNAL ;
    PORT
      LAYER M5 ;
        RECT 109.200 267.648 109.224 267.840 ;
    END
  END out_res[435]
  PIN out_res[436]
    DIRECTION OUTPUT ;
    USE SIGNAL ;
    PORT
      LAYER M5 ;
        RECT 109.440 267.648 109.464 267.840 ;
    END
  END out_res[436]
  PIN out_res[437]
    DIRECTION OUTPUT ;
    USE SIGNAL ;
    PORT
      LAYER M5 ;
        RECT 109.680 267.648 109.704 267.840 ;
    END
  END out_res[437]
  PIN out_res[438]
    DIRECTION OUTPUT ;
    USE SIGNAL ;
    PORT
      LAYER M5 ;
        RECT 109.920 267.648 109.944 267.840 ;
    END
  END out_res[438]
  PIN out_res[439]
    DIRECTION OUTPUT ;
    USE SIGNAL ;
    PORT
      LAYER M5 ;
        RECT 110.160 267.648 110.184 267.840 ;
    END
  END out_res[439]
  PIN out_res[440]
    DIRECTION OUTPUT ;
    USE SIGNAL ;
    PORT
      LAYER M5 ;
        RECT 110.400 267.648 110.424 267.840 ;
    END
  END out_res[440]
  PIN out_res[441]
    DIRECTION OUTPUT ;
    USE SIGNAL ;
    PORT
      LAYER M5 ;
        RECT 110.640 267.648 110.664 267.840 ;
    END
  END out_res[441]
  PIN out_res[442]
    DIRECTION OUTPUT ;
    USE SIGNAL ;
    PORT
      LAYER M5 ;
        RECT 110.880 267.648 110.904 267.840 ;
    END
  END out_res[442]
  PIN out_res[443]
    DIRECTION OUTPUT ;
    USE SIGNAL ;
    PORT
      LAYER M5 ;
        RECT 111.120 267.648 111.144 267.840 ;
    END
  END out_res[443]
  PIN out_res[444]
    DIRECTION OUTPUT ;
    USE SIGNAL ;
    PORT
      LAYER M5 ;
        RECT 111.360 267.648 111.384 267.840 ;
    END
  END out_res[444]
  PIN out_res[445]
    DIRECTION OUTPUT ;
    USE SIGNAL ;
    PORT
      LAYER M5 ;
        RECT 111.600 267.648 111.624 267.840 ;
    END
  END out_res[445]
  PIN out_res[446]
    DIRECTION OUTPUT ;
    USE SIGNAL ;
    PORT
      LAYER M5 ;
        RECT 111.840 267.648 111.864 267.840 ;
    END
  END out_res[446]
  PIN out_res[447]
    DIRECTION OUTPUT ;
    USE SIGNAL ;
    PORT
      LAYER M5 ;
        RECT 112.080 267.648 112.104 267.840 ;
    END
  END out_res[447]
  PIN out_res[448]
    DIRECTION OUTPUT ;
    USE SIGNAL ;
    PORT
      LAYER M5 ;
        RECT 112.320 267.648 112.344 267.840 ;
    END
  END out_res[448]
  PIN out_res[449]
    DIRECTION OUTPUT ;
    USE SIGNAL ;
    PORT
      LAYER M5 ;
        RECT 112.560 267.648 112.584 267.840 ;
    END
  END out_res[449]
  PIN out_res[450]
    DIRECTION OUTPUT ;
    USE SIGNAL ;
    PORT
      LAYER M5 ;
        RECT 112.800 267.648 112.824 267.840 ;
    END
  END out_res[450]
  PIN out_res[451]
    DIRECTION OUTPUT ;
    USE SIGNAL ;
    PORT
      LAYER M5 ;
        RECT 113.040 267.648 113.064 267.840 ;
    END
  END out_res[451]
  PIN out_res[452]
    DIRECTION OUTPUT ;
    USE SIGNAL ;
    PORT
      LAYER M5 ;
        RECT 113.280 267.648 113.304 267.840 ;
    END
  END out_res[452]
  PIN out_res[453]
    DIRECTION OUTPUT ;
    USE SIGNAL ;
    PORT
      LAYER M5 ;
        RECT 113.520 267.648 113.544 267.840 ;
    END
  END out_res[453]
  PIN out_res[454]
    DIRECTION OUTPUT ;
    USE SIGNAL ;
    PORT
      LAYER M5 ;
        RECT 113.760 267.648 113.784 267.840 ;
    END
  END out_res[454]
  PIN out_res[455]
    DIRECTION OUTPUT ;
    USE SIGNAL ;
    PORT
      LAYER M5 ;
        RECT 114.000 267.648 114.024 267.840 ;
    END
  END out_res[455]
  PIN out_res[456]
    DIRECTION OUTPUT ;
    USE SIGNAL ;
    PORT
      LAYER M5 ;
        RECT 114.240 267.648 114.264 267.840 ;
    END
  END out_res[456]
  PIN out_res[457]
    DIRECTION OUTPUT ;
    USE SIGNAL ;
    PORT
      LAYER M5 ;
        RECT 114.480 267.648 114.504 267.840 ;
    END
  END out_res[457]
  PIN out_res[458]
    DIRECTION OUTPUT ;
    USE SIGNAL ;
    PORT
      LAYER M5 ;
        RECT 114.720 267.648 114.744 267.840 ;
    END
  END out_res[458]
  PIN out_res[459]
    DIRECTION OUTPUT ;
    USE SIGNAL ;
    PORT
      LAYER M5 ;
        RECT 114.960 267.648 114.984 267.840 ;
    END
  END out_res[459]
  PIN out_res[460]
    DIRECTION OUTPUT ;
    USE SIGNAL ;
    PORT
      LAYER M5 ;
        RECT 115.200 267.648 115.224 267.840 ;
    END
  END out_res[460]
  PIN out_res[461]
    DIRECTION OUTPUT ;
    USE SIGNAL ;
    PORT
      LAYER M5 ;
        RECT 115.440 267.648 115.464 267.840 ;
    END
  END out_res[461]
  PIN out_res[462]
    DIRECTION OUTPUT ;
    USE SIGNAL ;
    PORT
      LAYER M5 ;
        RECT 115.680 267.648 115.704 267.840 ;
    END
  END out_res[462]
  PIN out_res[463]
    DIRECTION OUTPUT ;
    USE SIGNAL ;
    PORT
      LAYER M5 ;
        RECT 115.920 267.648 115.944 267.840 ;
    END
  END out_res[463]
  PIN out_res[464]
    DIRECTION OUTPUT ;
    USE SIGNAL ;
    PORT
      LAYER M5 ;
        RECT 116.160 267.648 116.184 267.840 ;
    END
  END out_res[464]
  PIN out_res[465]
    DIRECTION OUTPUT ;
    USE SIGNAL ;
    PORT
      LAYER M5 ;
        RECT 116.400 267.648 116.424 267.840 ;
    END
  END out_res[465]
  PIN out_res[466]
    DIRECTION OUTPUT ;
    USE SIGNAL ;
    PORT
      LAYER M5 ;
        RECT 116.640 267.648 116.664 267.840 ;
    END
  END out_res[466]
  PIN out_res[467]
    DIRECTION OUTPUT ;
    USE SIGNAL ;
    PORT
      LAYER M5 ;
        RECT 116.880 267.648 116.904 267.840 ;
    END
  END out_res[467]
  PIN out_res[468]
    DIRECTION OUTPUT ;
    USE SIGNAL ;
    PORT
      LAYER M5 ;
        RECT 117.120 267.648 117.144 267.840 ;
    END
  END out_res[468]
  PIN out_res[469]
    DIRECTION OUTPUT ;
    USE SIGNAL ;
    PORT
      LAYER M5 ;
        RECT 117.360 267.648 117.384 267.840 ;
    END
  END out_res[469]
  PIN out_res[470]
    DIRECTION OUTPUT ;
    USE SIGNAL ;
    PORT
      LAYER M5 ;
        RECT 117.600 267.648 117.624 267.840 ;
    END
  END out_res[470]
  PIN out_res[471]
    DIRECTION OUTPUT ;
    USE SIGNAL ;
    PORT
      LAYER M5 ;
        RECT 117.840 267.648 117.864 267.840 ;
    END
  END out_res[471]
  PIN out_res[472]
    DIRECTION OUTPUT ;
    USE SIGNAL ;
    PORT
      LAYER M5 ;
        RECT 118.080 267.648 118.104 267.840 ;
    END
  END out_res[472]
  PIN out_res[473]
    DIRECTION OUTPUT ;
    USE SIGNAL ;
    PORT
      LAYER M5 ;
        RECT 118.320 267.648 118.344 267.840 ;
    END
  END out_res[473]
  PIN out_res[474]
    DIRECTION OUTPUT ;
    USE SIGNAL ;
    PORT
      LAYER M5 ;
        RECT 118.560 267.648 118.584 267.840 ;
    END
  END out_res[474]
  PIN out_res[475]
    DIRECTION OUTPUT ;
    USE SIGNAL ;
    PORT
      LAYER M5 ;
        RECT 118.800 267.648 118.824 267.840 ;
    END
  END out_res[475]
  PIN out_res[476]
    DIRECTION OUTPUT ;
    USE SIGNAL ;
    PORT
      LAYER M5 ;
        RECT 119.040 267.648 119.064 267.840 ;
    END
  END out_res[476]
  PIN out_res[477]
    DIRECTION OUTPUT ;
    USE SIGNAL ;
    PORT
      LAYER M5 ;
        RECT 119.280 267.648 119.304 267.840 ;
    END
  END out_res[477]
  PIN out_res[478]
    DIRECTION OUTPUT ;
    USE SIGNAL ;
    PORT
      LAYER M5 ;
        RECT 119.520 267.648 119.544 267.840 ;
    END
  END out_res[478]
  PIN out_res[479]
    DIRECTION OUTPUT ;
    USE SIGNAL ;
    PORT
      LAYER M5 ;
        RECT 119.760 267.648 119.784 267.840 ;
    END
  END out_res[479]
  PIN out_res[480]
    DIRECTION OUTPUT ;
    USE SIGNAL ;
    PORT
      LAYER M5 ;
        RECT 120.000 267.648 120.024 267.840 ;
    END
  END out_res[480]
  PIN out_res[481]
    DIRECTION OUTPUT ;
    USE SIGNAL ;
    PORT
      LAYER M5 ;
        RECT 120.240 267.648 120.264 267.840 ;
    END
  END out_res[481]
  PIN out_res[482]
    DIRECTION OUTPUT ;
    USE SIGNAL ;
    PORT
      LAYER M5 ;
        RECT 120.480 267.648 120.504 267.840 ;
    END
  END out_res[482]
  PIN out_res[483]
    DIRECTION OUTPUT ;
    USE SIGNAL ;
    PORT
      LAYER M5 ;
        RECT 120.720 267.648 120.744 267.840 ;
    END
  END out_res[483]
  PIN out_res[484]
    DIRECTION OUTPUT ;
    USE SIGNAL ;
    PORT
      LAYER M5 ;
        RECT 120.960 267.648 120.984 267.840 ;
    END
  END out_res[484]
  PIN out_res[485]
    DIRECTION OUTPUT ;
    USE SIGNAL ;
    PORT
      LAYER M5 ;
        RECT 121.200 267.648 121.224 267.840 ;
    END
  END out_res[485]
  PIN out_res[486]
    DIRECTION OUTPUT ;
    USE SIGNAL ;
    PORT
      LAYER M5 ;
        RECT 121.440 267.648 121.464 267.840 ;
    END
  END out_res[486]
  PIN out_res[487]
    DIRECTION OUTPUT ;
    USE SIGNAL ;
    PORT
      LAYER M5 ;
        RECT 121.680 267.648 121.704 267.840 ;
    END
  END out_res[487]
  PIN out_res[488]
    DIRECTION OUTPUT ;
    USE SIGNAL ;
    PORT
      LAYER M5 ;
        RECT 121.920 267.648 121.944 267.840 ;
    END
  END out_res[488]
  PIN out_res[489]
    DIRECTION OUTPUT ;
    USE SIGNAL ;
    PORT
      LAYER M5 ;
        RECT 122.160 267.648 122.184 267.840 ;
    END
  END out_res[489]
  PIN out_res[490]
    DIRECTION OUTPUT ;
    USE SIGNAL ;
    PORT
      LAYER M5 ;
        RECT 122.400 267.648 122.424 267.840 ;
    END
  END out_res[490]
  PIN out_res[491]
    DIRECTION OUTPUT ;
    USE SIGNAL ;
    PORT
      LAYER M5 ;
        RECT 122.640 267.648 122.664 267.840 ;
    END
  END out_res[491]
  PIN out_res[492]
    DIRECTION OUTPUT ;
    USE SIGNAL ;
    PORT
      LAYER M5 ;
        RECT 122.880 267.648 122.904 267.840 ;
    END
  END out_res[492]
  PIN out_res[493]
    DIRECTION OUTPUT ;
    USE SIGNAL ;
    PORT
      LAYER M5 ;
        RECT 123.120 267.648 123.144 267.840 ;
    END
  END out_res[493]
  PIN out_res[494]
    DIRECTION OUTPUT ;
    USE SIGNAL ;
    PORT
      LAYER M5 ;
        RECT 123.360 267.648 123.384 267.840 ;
    END
  END out_res[494]
  PIN out_res[495]
    DIRECTION OUTPUT ;
    USE SIGNAL ;
    PORT
      LAYER M5 ;
        RECT 123.600 267.648 123.624 267.840 ;
    END
  END out_res[495]
  PIN out_res[496]
    DIRECTION OUTPUT ;
    USE SIGNAL ;
    PORT
      LAYER M5 ;
        RECT 123.840 267.648 123.864 267.840 ;
    END
  END out_res[496]
  PIN out_res[497]
    DIRECTION OUTPUT ;
    USE SIGNAL ;
    PORT
      LAYER M5 ;
        RECT 124.080 267.648 124.104 267.840 ;
    END
  END out_res[497]
  PIN out_res[498]
    DIRECTION OUTPUT ;
    USE SIGNAL ;
    PORT
      LAYER M5 ;
        RECT 124.320 267.648 124.344 267.840 ;
    END
  END out_res[498]
  PIN out_res[499]
    DIRECTION OUTPUT ;
    USE SIGNAL ;
    PORT
      LAYER M5 ;
        RECT 124.560 267.648 124.584 267.840 ;
    END
  END out_res[499]
  PIN out_res[500]
    DIRECTION OUTPUT ;
    USE SIGNAL ;
    PORT
      LAYER M5 ;
        RECT 124.800 267.648 124.824 267.840 ;
    END
  END out_res[500]
  PIN out_res[501]
    DIRECTION OUTPUT ;
    USE SIGNAL ;
    PORT
      LAYER M5 ;
        RECT 125.040 267.648 125.064 267.840 ;
    END
  END out_res[501]
  PIN out_res[502]
    DIRECTION OUTPUT ;
    USE SIGNAL ;
    PORT
      LAYER M5 ;
        RECT 125.280 267.648 125.304 267.840 ;
    END
  END out_res[502]
  PIN out_res[503]
    DIRECTION OUTPUT ;
    USE SIGNAL ;
    PORT
      LAYER M5 ;
        RECT 125.520 267.648 125.544 267.840 ;
    END
  END out_res[503]
  PIN out_res[504]
    DIRECTION OUTPUT ;
    USE SIGNAL ;
    PORT
      LAYER M5 ;
        RECT 125.760 267.648 125.784 267.840 ;
    END
  END out_res[504]
  PIN out_res[505]
    DIRECTION OUTPUT ;
    USE SIGNAL ;
    PORT
      LAYER M5 ;
        RECT 126.000 267.648 126.024 267.840 ;
    END
  END out_res[505]
  PIN out_res[506]
    DIRECTION OUTPUT ;
    USE SIGNAL ;
    PORT
      LAYER M5 ;
        RECT 126.240 267.648 126.264 267.840 ;
    END
  END out_res[506]
  PIN out_res[507]
    DIRECTION OUTPUT ;
    USE SIGNAL ;
    PORT
      LAYER M5 ;
        RECT 126.480 267.648 126.504 267.840 ;
    END
  END out_res[507]
  PIN out_res[508]
    DIRECTION OUTPUT ;
    USE SIGNAL ;
    PORT
      LAYER M5 ;
        RECT 126.720 267.648 126.744 267.840 ;
    END
  END out_res[508]
  PIN out_res[509]
    DIRECTION OUTPUT ;
    USE SIGNAL ;
    PORT
      LAYER M5 ;
        RECT 126.960 267.648 126.984 267.840 ;
    END
  END out_res[509]
  PIN out_res[510]
    DIRECTION OUTPUT ;
    USE SIGNAL ;
    PORT
      LAYER M5 ;
        RECT 127.200 267.648 127.224 267.840 ;
    END
  END out_res[510]
  PIN out_res[511]
    DIRECTION OUTPUT ;
    USE SIGNAL ;
    PORT
      LAYER M5 ;
        RECT 127.440 267.648 127.464 267.840 ;
    END
  END out_res[511]
  PIN out_res[512]
    DIRECTION OUTPUT ;
    USE SIGNAL ;
    PORT
      LAYER M5 ;
        RECT 127.680 267.648 127.704 267.840 ;
    END
  END out_res[512]
  PIN out_res[513]
    DIRECTION OUTPUT ;
    USE SIGNAL ;
    PORT
      LAYER M5 ;
        RECT 127.920 267.648 127.944 267.840 ;
    END
  END out_res[513]
  PIN out_res[514]
    DIRECTION OUTPUT ;
    USE SIGNAL ;
    PORT
      LAYER M5 ;
        RECT 128.160 267.648 128.184 267.840 ;
    END
  END out_res[514]
  PIN out_res[515]
    DIRECTION OUTPUT ;
    USE SIGNAL ;
    PORT
      LAYER M5 ;
        RECT 128.400 267.648 128.424 267.840 ;
    END
  END out_res[515]
  PIN out_res[516]
    DIRECTION OUTPUT ;
    USE SIGNAL ;
    PORT
      LAYER M5 ;
        RECT 128.640 267.648 128.664 267.840 ;
    END
  END out_res[516]
  PIN out_res[517]
    DIRECTION OUTPUT ;
    USE SIGNAL ;
    PORT
      LAYER M5 ;
        RECT 128.880 267.648 128.904 267.840 ;
    END
  END out_res[517]
  PIN out_res[518]
    DIRECTION OUTPUT ;
    USE SIGNAL ;
    PORT
      LAYER M5 ;
        RECT 129.120 267.648 129.144 267.840 ;
    END
  END out_res[518]
  PIN out_res[519]
    DIRECTION OUTPUT ;
    USE SIGNAL ;
    PORT
      LAYER M5 ;
        RECT 129.360 267.648 129.384 267.840 ;
    END
  END out_res[519]
  PIN out_res[520]
    DIRECTION OUTPUT ;
    USE SIGNAL ;
    PORT
      LAYER M5 ;
        RECT 129.600 267.648 129.624 267.840 ;
    END
  END out_res[520]
  PIN out_res[521]
    DIRECTION OUTPUT ;
    USE SIGNAL ;
    PORT
      LAYER M5 ;
        RECT 129.840 267.648 129.864 267.840 ;
    END
  END out_res[521]
  PIN out_res[522]
    DIRECTION OUTPUT ;
    USE SIGNAL ;
    PORT
      LAYER M5 ;
        RECT 130.080 267.648 130.104 267.840 ;
    END
  END out_res[522]
  PIN out_res[523]
    DIRECTION OUTPUT ;
    USE SIGNAL ;
    PORT
      LAYER M5 ;
        RECT 130.320 267.648 130.344 267.840 ;
    END
  END out_res[523]
  PIN out_res[524]
    DIRECTION OUTPUT ;
    USE SIGNAL ;
    PORT
      LAYER M5 ;
        RECT 130.560 267.648 130.584 267.840 ;
    END
  END out_res[524]
  PIN out_res[525]
    DIRECTION OUTPUT ;
    USE SIGNAL ;
    PORT
      LAYER M5 ;
        RECT 130.800 267.648 130.824 267.840 ;
    END
  END out_res[525]
  PIN out_res[526]
    DIRECTION OUTPUT ;
    USE SIGNAL ;
    PORT
      LAYER M5 ;
        RECT 131.040 267.648 131.064 267.840 ;
    END
  END out_res[526]
  PIN out_res[527]
    DIRECTION OUTPUT ;
    USE SIGNAL ;
    PORT
      LAYER M5 ;
        RECT 131.280 267.648 131.304 267.840 ;
    END
  END out_res[527]
  PIN out_res[528]
    DIRECTION OUTPUT ;
    USE SIGNAL ;
    PORT
      LAYER M5 ;
        RECT 131.520 267.648 131.544 267.840 ;
    END
  END out_res[528]
  PIN out_res[529]
    DIRECTION OUTPUT ;
    USE SIGNAL ;
    PORT
      LAYER M5 ;
        RECT 131.760 267.648 131.784 267.840 ;
    END
  END out_res[529]
  PIN out_res[530]
    DIRECTION OUTPUT ;
    USE SIGNAL ;
    PORT
      LAYER M5 ;
        RECT 132.000 267.648 132.024 267.840 ;
    END
  END out_res[530]
  PIN out_res[531]
    DIRECTION OUTPUT ;
    USE SIGNAL ;
    PORT
      LAYER M5 ;
        RECT 132.240 267.648 132.264 267.840 ;
    END
  END out_res[531]
  PIN out_res[532]
    DIRECTION OUTPUT ;
    USE SIGNAL ;
    PORT
      LAYER M5 ;
        RECT 132.480 267.648 132.504 267.840 ;
    END
  END out_res[532]
  PIN out_res[533]
    DIRECTION OUTPUT ;
    USE SIGNAL ;
    PORT
      LAYER M5 ;
        RECT 132.720 267.648 132.744 267.840 ;
    END
  END out_res[533]
  PIN out_res[534]
    DIRECTION OUTPUT ;
    USE SIGNAL ;
    PORT
      LAYER M5 ;
        RECT 132.960 267.648 132.984 267.840 ;
    END
  END out_res[534]
  PIN out_res[535]
    DIRECTION OUTPUT ;
    USE SIGNAL ;
    PORT
      LAYER M5 ;
        RECT 133.200 267.648 133.224 267.840 ;
    END
  END out_res[535]
  PIN out_res[536]
    DIRECTION OUTPUT ;
    USE SIGNAL ;
    PORT
      LAYER M5 ;
        RECT 133.440 267.648 133.464 267.840 ;
    END
  END out_res[536]
  PIN out_res[537]
    DIRECTION OUTPUT ;
    USE SIGNAL ;
    PORT
      LAYER M5 ;
        RECT 133.680 267.648 133.704 267.840 ;
    END
  END out_res[537]
  PIN out_res[538]
    DIRECTION OUTPUT ;
    USE SIGNAL ;
    PORT
      LAYER M5 ;
        RECT 133.920 267.648 133.944 267.840 ;
    END
  END out_res[538]
  PIN out_res[539]
    DIRECTION OUTPUT ;
    USE SIGNAL ;
    PORT
      LAYER M5 ;
        RECT 134.160 267.648 134.184 267.840 ;
    END
  END out_res[539]
  PIN out_res[540]
    DIRECTION OUTPUT ;
    USE SIGNAL ;
    PORT
      LAYER M5 ;
        RECT 134.400 267.648 134.424 267.840 ;
    END
  END out_res[540]
  PIN out_res[541]
    DIRECTION OUTPUT ;
    USE SIGNAL ;
    PORT
      LAYER M5 ;
        RECT 134.640 267.648 134.664 267.840 ;
    END
  END out_res[541]
  PIN out_res[542]
    DIRECTION OUTPUT ;
    USE SIGNAL ;
    PORT
      LAYER M5 ;
        RECT 134.880 267.648 134.904 267.840 ;
    END
  END out_res[542]
  PIN out_res[543]
    DIRECTION OUTPUT ;
    USE SIGNAL ;
    PORT
      LAYER M5 ;
        RECT 135.120 267.648 135.144 267.840 ;
    END
  END out_res[543]
  PIN out_res[544]
    DIRECTION OUTPUT ;
    USE SIGNAL ;
    PORT
      LAYER M5 ;
        RECT 135.360 267.648 135.384 267.840 ;
    END
  END out_res[544]
  PIN out_res[545]
    DIRECTION OUTPUT ;
    USE SIGNAL ;
    PORT
      LAYER M5 ;
        RECT 135.600 267.648 135.624 267.840 ;
    END
  END out_res[545]
  PIN out_res[546]
    DIRECTION OUTPUT ;
    USE SIGNAL ;
    PORT
      LAYER M5 ;
        RECT 135.840 267.648 135.864 267.840 ;
    END
  END out_res[546]
  PIN out_res[547]
    DIRECTION OUTPUT ;
    USE SIGNAL ;
    PORT
      LAYER M5 ;
        RECT 136.080 267.648 136.104 267.840 ;
    END
  END out_res[547]
  PIN out_res[548]
    DIRECTION OUTPUT ;
    USE SIGNAL ;
    PORT
      LAYER M5 ;
        RECT 136.320 267.648 136.344 267.840 ;
    END
  END out_res[548]
  PIN out_res[549]
    DIRECTION OUTPUT ;
    USE SIGNAL ;
    PORT
      LAYER M5 ;
        RECT 136.560 267.648 136.584 267.840 ;
    END
  END out_res[549]
  PIN out_res[550]
    DIRECTION OUTPUT ;
    USE SIGNAL ;
    PORT
      LAYER M5 ;
        RECT 136.800 267.648 136.824 267.840 ;
    END
  END out_res[550]
  PIN out_res[551]
    DIRECTION OUTPUT ;
    USE SIGNAL ;
    PORT
      LAYER M5 ;
        RECT 137.040 267.648 137.064 267.840 ;
    END
  END out_res[551]
  PIN out_res[552]
    DIRECTION OUTPUT ;
    USE SIGNAL ;
    PORT
      LAYER M5 ;
        RECT 137.280 267.648 137.304 267.840 ;
    END
  END out_res[552]
  PIN out_res[553]
    DIRECTION OUTPUT ;
    USE SIGNAL ;
    PORT
      LAYER M5 ;
        RECT 137.520 267.648 137.544 267.840 ;
    END
  END out_res[553]
  PIN out_res[554]
    DIRECTION OUTPUT ;
    USE SIGNAL ;
    PORT
      LAYER M5 ;
        RECT 137.760 267.648 137.784 267.840 ;
    END
  END out_res[554]
  PIN out_res[555]
    DIRECTION OUTPUT ;
    USE SIGNAL ;
    PORT
      LAYER M5 ;
        RECT 138.000 267.648 138.024 267.840 ;
    END
  END out_res[555]
  PIN out_res[556]
    DIRECTION OUTPUT ;
    USE SIGNAL ;
    PORT
      LAYER M5 ;
        RECT 138.240 267.648 138.264 267.840 ;
    END
  END out_res[556]
  PIN out_res[557]
    DIRECTION OUTPUT ;
    USE SIGNAL ;
    PORT
      LAYER M5 ;
        RECT 138.480 267.648 138.504 267.840 ;
    END
  END out_res[557]
  PIN out_res[558]
    DIRECTION OUTPUT ;
    USE SIGNAL ;
    PORT
      LAYER M5 ;
        RECT 138.720 267.648 138.744 267.840 ;
    END
  END out_res[558]
  PIN out_res[559]
    DIRECTION OUTPUT ;
    USE SIGNAL ;
    PORT
      LAYER M5 ;
        RECT 138.960 267.648 138.984 267.840 ;
    END
  END out_res[559]
  PIN out_res[560]
    DIRECTION OUTPUT ;
    USE SIGNAL ;
    PORT
      LAYER M5 ;
        RECT 139.200 267.648 139.224 267.840 ;
    END
  END out_res[560]
  PIN out_res[561]
    DIRECTION OUTPUT ;
    USE SIGNAL ;
    PORT
      LAYER M5 ;
        RECT 139.440 267.648 139.464 267.840 ;
    END
  END out_res[561]
  PIN out_res[562]
    DIRECTION OUTPUT ;
    USE SIGNAL ;
    PORT
      LAYER M5 ;
        RECT 139.680 267.648 139.704 267.840 ;
    END
  END out_res[562]
  PIN out_res[563]
    DIRECTION OUTPUT ;
    USE SIGNAL ;
    PORT
      LAYER M5 ;
        RECT 139.920 267.648 139.944 267.840 ;
    END
  END out_res[563]
  PIN out_res[564]
    DIRECTION OUTPUT ;
    USE SIGNAL ;
    PORT
      LAYER M5 ;
        RECT 140.160 267.648 140.184 267.840 ;
    END
  END out_res[564]
  PIN out_res[565]
    DIRECTION OUTPUT ;
    USE SIGNAL ;
    PORT
      LAYER M5 ;
        RECT 140.400 267.648 140.424 267.840 ;
    END
  END out_res[565]
  PIN out_res[566]
    DIRECTION OUTPUT ;
    USE SIGNAL ;
    PORT
      LAYER M5 ;
        RECT 140.640 267.648 140.664 267.840 ;
    END
  END out_res[566]
  PIN out_res[567]
    DIRECTION OUTPUT ;
    USE SIGNAL ;
    PORT
      LAYER M5 ;
        RECT 140.880 267.648 140.904 267.840 ;
    END
  END out_res[567]
  PIN out_res[568]
    DIRECTION OUTPUT ;
    USE SIGNAL ;
    PORT
      LAYER M5 ;
        RECT 141.120 267.648 141.144 267.840 ;
    END
  END out_res[568]
  PIN out_res[569]
    DIRECTION OUTPUT ;
    USE SIGNAL ;
    PORT
      LAYER M5 ;
        RECT 141.360 267.648 141.384 267.840 ;
    END
  END out_res[569]
  PIN out_res[570]
    DIRECTION OUTPUT ;
    USE SIGNAL ;
    PORT
      LAYER M5 ;
        RECT 141.600 267.648 141.624 267.840 ;
    END
  END out_res[570]
  PIN out_res[571]
    DIRECTION OUTPUT ;
    USE SIGNAL ;
    PORT
      LAYER M5 ;
        RECT 141.840 267.648 141.864 267.840 ;
    END
  END out_res[571]
  PIN out_res[572]
    DIRECTION OUTPUT ;
    USE SIGNAL ;
    PORT
      LAYER M5 ;
        RECT 142.080 267.648 142.104 267.840 ;
    END
  END out_res[572]
  PIN out_res[573]
    DIRECTION OUTPUT ;
    USE SIGNAL ;
    PORT
      LAYER M5 ;
        RECT 142.320 267.648 142.344 267.840 ;
    END
  END out_res[573]
  PIN out_res[574]
    DIRECTION OUTPUT ;
    USE SIGNAL ;
    PORT
      LAYER M5 ;
        RECT 142.560 267.648 142.584 267.840 ;
    END
  END out_res[574]
  PIN out_res[575]
    DIRECTION OUTPUT ;
    USE SIGNAL ;
    PORT
      LAYER M5 ;
        RECT 142.800 267.648 142.824 267.840 ;
    END
  END out_res[575]
  PIN in_w[0]
    DIRECTION INPUT ;
    USE SIGNAL ;
    PORT
      LAYER M5 ;
        RECT 143.424 267.648 143.448 267.840 ;
    END
  END in_w[0]
  PIN in_w[1]
    DIRECTION INPUT ;
    USE SIGNAL ;
    PORT
      LAYER M5 ;
        RECT 143.664 267.648 143.688 267.840 ;
    END
  END in_w[1]
  PIN in_w[2]
    DIRECTION INPUT ;
    USE SIGNAL ;
    PORT
      LAYER M5 ;
        RECT 143.904 267.648 143.928 267.840 ;
    END
  END in_w[2]
  PIN in_w[3]
    DIRECTION INPUT ;
    USE SIGNAL ;
    PORT
      LAYER M5 ;
        RECT 144.144 267.648 144.168 267.840 ;
    END
  END in_w[3]
  PIN in_w[4]
    DIRECTION INPUT ;
    USE SIGNAL ;
    PORT
      LAYER M5 ;
        RECT 144.384 267.648 144.408 267.840 ;
    END
  END in_w[4]
  PIN in_w[5]
    DIRECTION INPUT ;
    USE SIGNAL ;
    PORT
      LAYER M5 ;
        RECT 144.624 267.648 144.648 267.840 ;
    END
  END in_w[5]
  PIN in_w[6]
    DIRECTION INPUT ;
    USE SIGNAL ;
    PORT
      LAYER M5 ;
        RECT 144.864 267.648 144.888 267.840 ;
    END
  END in_w[6]
  PIN in_w[7]
    DIRECTION INPUT ;
    USE SIGNAL ;
    PORT
      LAYER M5 ;
        RECT 145.104 267.648 145.128 267.840 ;
    END
  END in_w[7]
  PIN in_w[8]
    DIRECTION INPUT ;
    USE SIGNAL ;
    PORT
      LAYER M5 ;
        RECT 145.344 267.648 145.368 267.840 ;
    END
  END in_w[8]
  PIN in_w[9]
    DIRECTION INPUT ;
    USE SIGNAL ;
    PORT
      LAYER M5 ;
        RECT 145.584 267.648 145.608 267.840 ;
    END
  END in_w[9]
  PIN in_w[10]
    DIRECTION INPUT ;
    USE SIGNAL ;
    PORT
      LAYER M5 ;
        RECT 145.824 267.648 145.848 267.840 ;
    END
  END in_w[10]
  PIN in_w[11]
    DIRECTION INPUT ;
    USE SIGNAL ;
    PORT
      LAYER M5 ;
        RECT 146.064 267.648 146.088 267.840 ;
    END
  END in_w[11]
  PIN in_w[12]
    DIRECTION INPUT ;
    USE SIGNAL ;
    PORT
      LAYER M5 ;
        RECT 146.304 267.648 146.328 267.840 ;
    END
  END in_w[12]
  PIN in_w[13]
    DIRECTION INPUT ;
    USE SIGNAL ;
    PORT
      LAYER M5 ;
        RECT 146.544 267.648 146.568 267.840 ;
    END
  END in_w[13]
  PIN in_w[14]
    DIRECTION INPUT ;
    USE SIGNAL ;
    PORT
      LAYER M5 ;
        RECT 146.784 267.648 146.808 267.840 ;
    END
  END in_w[14]
  PIN in_w[15]
    DIRECTION INPUT ;
    USE SIGNAL ;
    PORT
      LAYER M5 ;
        RECT 147.024 267.648 147.048 267.840 ;
    END
  END in_w[15]
  PIN in_w[16]
    DIRECTION INPUT ;
    USE SIGNAL ;
    PORT
      LAYER M5 ;
        RECT 147.264 267.648 147.288 267.840 ;
    END
  END in_w[16]
  PIN in_w[17]
    DIRECTION INPUT ;
    USE SIGNAL ;
    PORT
      LAYER M5 ;
        RECT 147.504 267.648 147.528 267.840 ;
    END
  END in_w[17]
  PIN in_w[18]
    DIRECTION INPUT ;
    USE SIGNAL ;
    PORT
      LAYER M5 ;
        RECT 147.744 267.648 147.768 267.840 ;
    END
  END in_w[18]
  PIN in_w[19]
    DIRECTION INPUT ;
    USE SIGNAL ;
    PORT
      LAYER M5 ;
        RECT 147.984 267.648 148.008 267.840 ;
    END
  END in_w[19]
  PIN in_w[20]
    DIRECTION INPUT ;
    USE SIGNAL ;
    PORT
      LAYER M5 ;
        RECT 148.224 267.648 148.248 267.840 ;
    END
  END in_w[20]
  PIN in_w[21]
    DIRECTION INPUT ;
    USE SIGNAL ;
    PORT
      LAYER M5 ;
        RECT 148.464 267.648 148.488 267.840 ;
    END
  END in_w[21]
  PIN in_w[22]
    DIRECTION INPUT ;
    USE SIGNAL ;
    PORT
      LAYER M5 ;
        RECT 148.704 267.648 148.728 267.840 ;
    END
  END in_w[22]
  PIN in_w[23]
    DIRECTION INPUT ;
    USE SIGNAL ;
    PORT
      LAYER M5 ;
        RECT 148.944 267.648 148.968 267.840 ;
    END
  END in_w[23]
  PIN in_w[24]
    DIRECTION INPUT ;
    USE SIGNAL ;
    PORT
      LAYER M5 ;
        RECT 149.184 267.648 149.208 267.840 ;
    END
  END in_w[24]
  PIN in_w[25]
    DIRECTION INPUT ;
    USE SIGNAL ;
    PORT
      LAYER M5 ;
        RECT 149.424 267.648 149.448 267.840 ;
    END
  END in_w[25]
  PIN in_w[26]
    DIRECTION INPUT ;
    USE SIGNAL ;
    PORT
      LAYER M5 ;
        RECT 149.664 267.648 149.688 267.840 ;
    END
  END in_w[26]
  PIN in_w[27]
    DIRECTION INPUT ;
    USE SIGNAL ;
    PORT
      LAYER M5 ;
        RECT 149.904 267.648 149.928 267.840 ;
    END
  END in_w[27]
  PIN in_w[28]
    DIRECTION INPUT ;
    USE SIGNAL ;
    PORT
      LAYER M5 ;
        RECT 150.144 267.648 150.168 267.840 ;
    END
  END in_w[28]
  PIN in_w[29]
    DIRECTION INPUT ;
    USE SIGNAL ;
    PORT
      LAYER M5 ;
        RECT 150.384 267.648 150.408 267.840 ;
    END
  END in_w[29]
  PIN in_w[30]
    DIRECTION INPUT ;
    USE SIGNAL ;
    PORT
      LAYER M5 ;
        RECT 150.624 267.648 150.648 267.840 ;
    END
  END in_w[30]
  PIN in_w[31]
    DIRECTION INPUT ;
    USE SIGNAL ;
    PORT
      LAYER M5 ;
        RECT 150.864 267.648 150.888 267.840 ;
    END
  END in_w[31]
  PIN in_w[32]
    DIRECTION INPUT ;
    USE SIGNAL ;
    PORT
      LAYER M5 ;
        RECT 151.104 267.648 151.128 267.840 ;
    END
  END in_w[32]
  PIN in_w[33]
    DIRECTION INPUT ;
    USE SIGNAL ;
    PORT
      LAYER M5 ;
        RECT 151.344 267.648 151.368 267.840 ;
    END
  END in_w[33]
  PIN in_w[34]
    DIRECTION INPUT ;
    USE SIGNAL ;
    PORT
      LAYER M5 ;
        RECT 151.584 267.648 151.608 267.840 ;
    END
  END in_w[34]
  PIN in_w[35]
    DIRECTION INPUT ;
    USE SIGNAL ;
    PORT
      LAYER M5 ;
        RECT 151.824 267.648 151.848 267.840 ;
    END
  END in_w[35]
  PIN in_w[36]
    DIRECTION INPUT ;
    USE SIGNAL ;
    PORT
      LAYER M5 ;
        RECT 152.064 267.648 152.088 267.840 ;
    END
  END in_w[36]
  PIN in_w[37]
    DIRECTION INPUT ;
    USE SIGNAL ;
    PORT
      LAYER M5 ;
        RECT 152.304 267.648 152.328 267.840 ;
    END
  END in_w[37]
  PIN in_w[38]
    DIRECTION INPUT ;
    USE SIGNAL ;
    PORT
      LAYER M5 ;
        RECT 152.544 267.648 152.568 267.840 ;
    END
  END in_w[38]
  PIN in_w[39]
    DIRECTION INPUT ;
    USE SIGNAL ;
    PORT
      LAYER M5 ;
        RECT 152.784 267.648 152.808 267.840 ;
    END
  END in_w[39]
  PIN in_w[40]
    DIRECTION INPUT ;
    USE SIGNAL ;
    PORT
      LAYER M5 ;
        RECT 153.024 267.648 153.048 267.840 ;
    END
  END in_w[40]
  PIN in_w[41]
    DIRECTION INPUT ;
    USE SIGNAL ;
    PORT
      LAYER M5 ;
        RECT 153.264 267.648 153.288 267.840 ;
    END
  END in_w[41]
  PIN in_w[42]
    DIRECTION INPUT ;
    USE SIGNAL ;
    PORT
      LAYER M5 ;
        RECT 153.504 267.648 153.528 267.840 ;
    END
  END in_w[42]
  PIN in_w[43]
    DIRECTION INPUT ;
    USE SIGNAL ;
    PORT
      LAYER M5 ;
        RECT 153.744 267.648 153.768 267.840 ;
    END
  END in_w[43]
  PIN in_w[44]
    DIRECTION INPUT ;
    USE SIGNAL ;
    PORT
      LAYER M5 ;
        RECT 153.984 267.648 154.008 267.840 ;
    END
  END in_w[44]
  PIN in_w[45]
    DIRECTION INPUT ;
    USE SIGNAL ;
    PORT
      LAYER M5 ;
        RECT 154.224 267.648 154.248 267.840 ;
    END
  END in_w[45]
  PIN in_w[46]
    DIRECTION INPUT ;
    USE SIGNAL ;
    PORT
      LAYER M5 ;
        RECT 154.464 267.648 154.488 267.840 ;
    END
  END in_w[46]
  PIN in_w[47]
    DIRECTION INPUT ;
    USE SIGNAL ;
    PORT
      LAYER M5 ;
        RECT 154.704 267.648 154.728 267.840 ;
    END
  END in_w[47]
  PIN in_w[48]
    DIRECTION INPUT ;
    USE SIGNAL ;
    PORT
      LAYER M5 ;
        RECT 154.944 267.648 154.968 267.840 ;
    END
  END in_w[48]
  PIN in_w[49]
    DIRECTION INPUT ;
    USE SIGNAL ;
    PORT
      LAYER M5 ;
        RECT 155.184 267.648 155.208 267.840 ;
    END
  END in_w[49]
  PIN in_w[50]
    DIRECTION INPUT ;
    USE SIGNAL ;
    PORT
      LAYER M5 ;
        RECT 155.424 267.648 155.448 267.840 ;
    END
  END in_w[50]
  PIN in_w[51]
    DIRECTION INPUT ;
    USE SIGNAL ;
    PORT
      LAYER M5 ;
        RECT 155.664 267.648 155.688 267.840 ;
    END
  END in_w[51]
  PIN in_w[52]
    DIRECTION INPUT ;
    USE SIGNAL ;
    PORT
      LAYER M5 ;
        RECT 155.904 267.648 155.928 267.840 ;
    END
  END in_w[52]
  PIN in_w[53]
    DIRECTION INPUT ;
    USE SIGNAL ;
    PORT
      LAYER M5 ;
        RECT 156.144 267.648 156.168 267.840 ;
    END
  END in_w[53]
  PIN in_w[54]
    DIRECTION INPUT ;
    USE SIGNAL ;
    PORT
      LAYER M5 ;
        RECT 156.384 267.648 156.408 267.840 ;
    END
  END in_w[54]
  PIN in_w[55]
    DIRECTION INPUT ;
    USE SIGNAL ;
    PORT
      LAYER M5 ;
        RECT 156.624 267.648 156.648 267.840 ;
    END
  END in_w[55]
  PIN in_w[56]
    DIRECTION INPUT ;
    USE SIGNAL ;
    PORT
      LAYER M5 ;
        RECT 156.864 267.648 156.888 267.840 ;
    END
  END in_w[56]
  PIN in_w[57]
    DIRECTION INPUT ;
    USE SIGNAL ;
    PORT
      LAYER M5 ;
        RECT 157.104 267.648 157.128 267.840 ;
    END
  END in_w[57]
  PIN in_w[58]
    DIRECTION INPUT ;
    USE SIGNAL ;
    PORT
      LAYER M5 ;
        RECT 157.344 267.648 157.368 267.840 ;
    END
  END in_w[58]
  PIN in_w[59]
    DIRECTION INPUT ;
    USE SIGNAL ;
    PORT
      LAYER M5 ;
        RECT 157.584 267.648 157.608 267.840 ;
    END
  END in_w[59]
  PIN in_w[60]
    DIRECTION INPUT ;
    USE SIGNAL ;
    PORT
      LAYER M5 ;
        RECT 157.824 267.648 157.848 267.840 ;
    END
  END in_w[60]
  PIN in_w[61]
    DIRECTION INPUT ;
    USE SIGNAL ;
    PORT
      LAYER M5 ;
        RECT 158.064 267.648 158.088 267.840 ;
    END
  END in_w[61]
  PIN in_w[62]
    DIRECTION INPUT ;
    USE SIGNAL ;
    PORT
      LAYER M5 ;
        RECT 158.304 267.648 158.328 267.840 ;
    END
  END in_w[62]
  PIN in_w[63]
    DIRECTION INPUT ;
    USE SIGNAL ;
    PORT
      LAYER M5 ;
        RECT 158.544 267.648 158.568 267.840 ;
    END
  END in_w[63]
  PIN in_w[64]
    DIRECTION INPUT ;
    USE SIGNAL ;
    PORT
      LAYER M5 ;
        RECT 158.784 267.648 158.808 267.840 ;
    END
  END in_w[64]
  PIN in_w[65]
    DIRECTION INPUT ;
    USE SIGNAL ;
    PORT
      LAYER M5 ;
        RECT 159.024 267.648 159.048 267.840 ;
    END
  END in_w[65]
  PIN in_w[66]
    DIRECTION INPUT ;
    USE SIGNAL ;
    PORT
      LAYER M5 ;
        RECT 159.264 267.648 159.288 267.840 ;
    END
  END in_w[66]
  PIN in_w[67]
    DIRECTION INPUT ;
    USE SIGNAL ;
    PORT
      LAYER M5 ;
        RECT 159.504 267.648 159.528 267.840 ;
    END
  END in_w[67]
  PIN ck
    DIRECTION INPUT ;
    USE CLOCK ;
    PORT
      LAYER M4 ;
        RECT 0.000 133.920 0.192 133.944 ;
    END
  END ck
  OBS
    LAYER M1 ;
      RECT 0.000 0.000 164.160 267.840 ;
    LAYER M2 ;
      RECT 0.000 0.000 164.160 267.840 ;
    LAYER M3 ;
      RECT 0.000 0.000 164.160 267.840 ;
    LAYER M4 ;
      RECT 0.000 0.000 164.160 267.840 ;
    LAYER M5 ;
      RECT 0.000 0.000 164.160 267.840 ;
  END
END dsdv_eng_rr_h0
END LIBRARY
